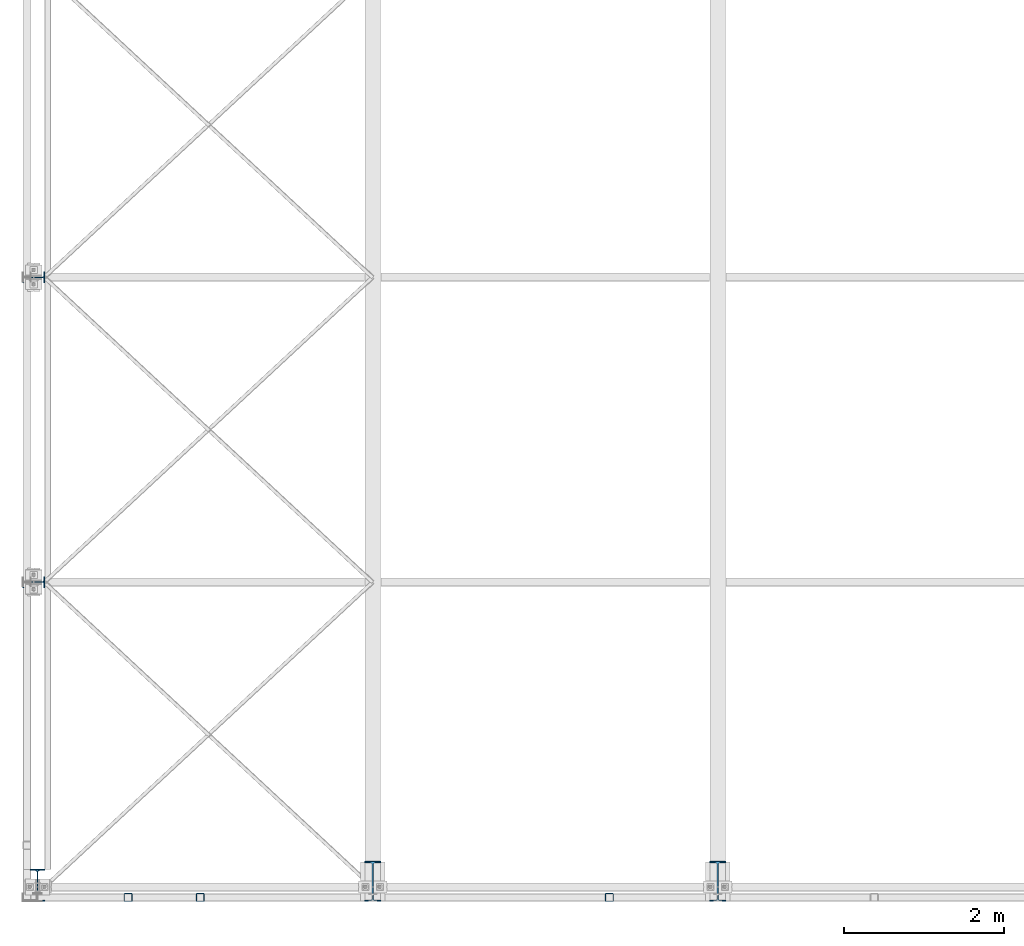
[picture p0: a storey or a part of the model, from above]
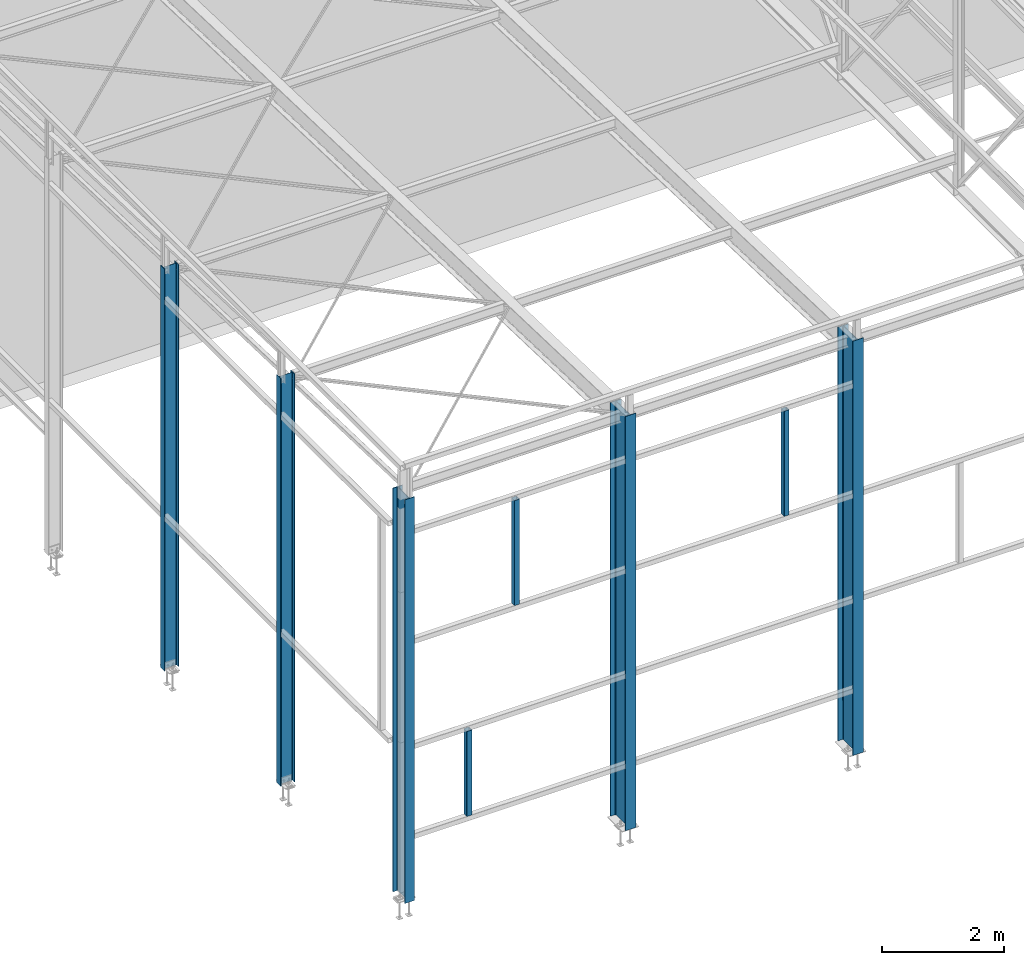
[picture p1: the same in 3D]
Properties of the parts of a building model (IFC2X3), part 1 of 2

# File
Description: ViewDefinition[CoordinationView_V2.0, QuantityTakeOffAddOnView]
File name: V.ifc
Time: 2017-08-30T17:55:49
Author: Gaël\Gaël_P
Organization: Structural Designer
Written by: IFC Database Version:Work
Made in: Tekla Structures 2016i Service Pack 3, IFC Export Version: 4.0.0.0 Jan 30 2017

# IfcSite, Undefined
RefElevation: 0 mm

# IfcBuildingStorey, Undefined
In: Undefined
Elevation: 0 mm

# IfcBeam: 4550*200 (2)
In: Undefined
Description: 4550*200; Material: CONCRETE/C25/30
Pset_BeamCommon - LoadBearing: yes; Reference: Po0(?)
Tekla Commun - Niveau bas: +0.000; Niveau haut: +4.550; Repère de pièce: Po0(?); Repère d'assemblage: Po0(?); Phase: 1; Classe: 1; Matériau: C25/30; Profil: 4550*200; Nom: POUTRE
Tekla Quantités - Surface par tonne: 4.4 m2; Hauteur: 4550 mm; Largeur: 200 mm
Name | Poids (kg) = NetWeight (kg) | Volume (m3) | Surface supérieure totale (m2) | Surface nette (m2) | Longueur (mm) | Length (mm) | OuterSurfaceArea (m2) | NetVolume (m3)
POUTRE | 29789.8 | 12.4 | 2.7 | 131.7 | 13732.4 | 13732.4 | 131.729 | 12.4124
POUTRE | 20484.3 | 8.5 | 1.9 | 91.3 | 9479.6 | 9479.56 | 91.2546 | 8.53511

# IfcBeam: 8550*200 (5)
In: Undefined
Description: 8550*200; Material: CONCRETE/C25/30
Tekla Commun - Niveau bas: +0.000; Niveau haut: +8.550; Repère de pièce: Po0(?); Repère d'assemblage: Po0(?); Phase: 1; Classe: 1; Matériau: C25/30; Profil: 8550*200; Nom: POUTRE
Tekla Quantités - Hauteur: 8550 mm; Largeur: 200 mm
Pset_BeamCommon - LoadBearing: yes; Reference: Po0(?)
Name | Poids (kg) = NetWeight (kg) | Volume (m3) | Surface supérieure totale (m2) | Surface par tonne (m2) | Surface nette (m2) | Longueur (mm) = Length (mm) | OuterSurfaceArea (m2) | NetVolume (m3)
POUTRE | 37962 | 15.8 | 1.9 | 4.4 | 165.3 | 9250 | 165.295 | 15.8175
POUTRE | 38372.4 | 16 | 1.9 | 4.4 | 167.8 | 9450 | 167.753 | 15.9885
POUTRE | 141998 | 59.2 | 6.9 | 4.3 | 610.3 | 34800 | 610.337 | 59.166
POUTRE | 38782.8 | 16.2 | 1.9 | 4.4 | 170.2 | 9650 | 170.212 | 16.1595
POUTRE | 201869 | 84.1 | 9.8 | 4.3 | 864.9 | 49296.2 | 864.929 | 84.112

# IfcBeam: HEA140 (4)
In: Undefined
Description: HEA140; Material: STEEL/S275-E28
Pset_BeamCommon - LoadBearing: yes
Tekla Commun - Repère d'assemblage: L0(?); Phase: 1; Classe: 2; Matériau: S275-E28; Profil: HEA140; Nom: LONGERON
Tekla Quantités - Volume: 0 m3; Surface par tonne: 32.2 m2; Hauteur: 133 mm; Largeur: 140 mm
Name | Reference = Repère de pièce | Niveau bas | Niveau haut | Poids (kg) | Surface supérieure totale (m2) | Surface nette (m2) | Longueur (mm) = Length (mm) | OuterSurfaceArea (m2) | NetVolume (m3) | NetWeight (kg)
LONGERON | L0 | +10.423 | +10.556 | 382.8 | 2.2 | 12.7 | 15520 | 12.3229 | 0.0468394 | 367.689
LONGERON | L0 | +11.236 | +11.369 | 382.8 | 2.2 | 12.7 | 15520 | 12.3229 | 0.0468394 | 367.689
LONGERON | L0 | +12.037 | +12.170 | 382.8 | 2.2 | 12.7 | 15520 | 12.3229 | 0.0468394 | 367.689
LONGERON | L0(?) | +7.117 | +7.250 | 371 | 2.1 | 12.3 | 15040 | 11.9418 | 0.0453907 | 356.317

# IfcBeam: HEA180, LONGERON
In: Undefined
Description: HEA180; Material: STEEL/S275-E28
Pset_BeamCommon - LoadBearing: yes; Reference: L0
Tekla Commun - Niveau bas: +7.079; Niveau haut: +7.250; Repère de pièce: L0; Repère d'assemblage: L0(?); Phase: 1; Classe: 2; Matériau: S275-E28; Profil: HEA180; Nom: LONGERON
Tekla Quantités - Poids: 545.3 kg; Volume: 0.1 m3; Surface supérieure totale: 2.8 m2; Surface par tonne: 28.8 m2; Surface nette: 16.1 m2; Hauteur: 171 mm; Largeur: 180 mm; Longueur: 15350 mm
BaseQuantities - Length: 15350 mm; OuterSurfaceArea: 15.7184 m2; NetVolume: 0.0664962 m3; NetWeight: 521.995 kg

# IfcBeam: HEA200, LONGERON
In: Undefined
Description: HEA200; Material: STEEL/S275-E28
Pset_BeamCommon - LoadBearing: yes; Reference: L0(?)
Tekla Commun - Niveau bas: +7.060; Niveau haut: +7.250; Repère de pièce: L0(?); Repère d'assemblage: L0(?); Phase: 1; Classe: 2; Matériau: S275-E28; Profil: HEA200; Nom: LONGERON
Tekla Quantités - Poids: 648.6 kg; Volume: 0.1 m3; Surface supérieure totale: 3.1 m2; Surface par tonne: 26.9 m2; Surface nette: 17.9 m2; Hauteur: 190 mm; Largeur: 200 mm; Longueur: 15350 mm
BaseQuantities - Length: 15350 mm; OuterSurfaceArea: 17.4376 m2; NetVolume: 0.0783617 m3; NetWeight: 615.14 kg

# IfcBeam: IPE120 (7)
In: Undefined
Description: IPE120; Material: STEEL/S275-E28
Tekla Commun - Repère d'assemblage: PN0(?); Phase: 1; Classe: 2; Matériau: S275-E28; Profil: IPE120; Nom: PANNE
Tekla Quantités - Volume: 0 m3; Surface supérieure totale: 0 m2; Surface par tonne: 45.8 m2; Hauteur: 120 mm; Largeur: 64 mm
Pset_BeamCommon - LoadBearing: yes
Name | Niveau bas | Niveau haut | Repère de pièce = Reference | Poids (kg) | Surface nette (m2) | Longueur (mm) = Length (mm) | OuterSurfaceArea (m2) | NetVolume (m3) | NetWeight (kg)
PANNE | +3.188 | +3.311 | PN0 | 114 | 5.4 | 11000 | 5.225 | 0.0140686 | 110.438 | Tekla Commun - Finition: GALVA
PANNE | +3.083 | +3.206 | PN0 | 114 | 5.4 | 11000 | 5.225 | 0.0140686 | 110.438 | Tekla Commun - Finition: GALVA
PANNE | +2.978 | +3.102 | PN0 | 114 | 5.4 | 11000 | 5.225 | 0.0140686 | 110.438 | Tekla Commun - Finition: GALVA
PANNE | +7.451 | +7.573 | PN0(?) | 11.6 | 0.5 | 1120 | 0.532 | 0.00143244 | 11.2446
PANNE | +7.571 | +7.693 | PN0(?) | 11.6 | 0.5 | 1120 | 0.532 | 0.00143244 | 11.2446
PANNE | +7.690 | +7.812 | PN0(?) | 11.6 | 0.5 | 1120 | 0.532 | 0.00143244 | 11.2446
PANNE | +7.810 | +7.932 | PN0(?) | 11.6 | 0.5 | 1120 | 0.532 | 0.00143244 | 11.2446

# IfcBeam: IPE160 (4)
In: Undefined
Description: IPE160; Material: STEEL/S275-E28
Tekla Commun - Niveau bas: +2.816; Niveau haut: +3.200; Repère de pièce: T0; Repère d'assemblage: T0(?); Finition: GALVA; Phase: 1; Classe: 2; Matériau: S275-E28; Profil: IPE160; Nom: TRAVERSE
Tekla Quantités - Poids: 67.7 kg; Volume: 0 m3; Surface supérieure totale: 0 m2; Surface par tonne: 39.5 m2; Surface nette: 2.7 m2; Hauteur: 160 mm; Largeur: 82 mm; Longueur: 4294.2 mm
Pset_BeamCommon - LoadBearing: yes; Reference: T0
BaseQuantities - Length: 4294.25 mm; OuterSurfaceArea: 2.67532 m2; NetVolume: 0.00831287 m3; NetWeight: 65.256 kg

# IfcBeam: IPE180 (5)
In: Undefined
Description: IPE180; Material: STEEL/S275-E28
Pset_BeamCommon - LoadBearing: yes; Reference: PN0(?)
Tekla Commun - Repère de pièce: PN0(?); Repère d'assemblage: PN0(?); Phase: 1; Classe: 2; Matériau: S275-E28; Profil: IPE180; Nom: PANNE
Tekla Quantités - Poids: 70 kg; Volume: 0 m3; Surface supérieure totale: 0 m2; Surface par tonne: 37.2 m2; Surface nette: 2.7 m2; Hauteur: 180 mm; Largeur: 91 mm; Longueur: 3730 mm
BaseQuantities - Length: 3730 mm; OuterSurfaceArea: 2.60354 m2; NetVolume: 0.008673 m3; NetWeight: 68.083 kg
Name | Niveau bas | Niveau haut
PANNE | +7.391 | +7.574
PANNE | +7.510 | +7.693
PANNE | +7.630 | +7.813
PANNE | +7.749 | +7.932
PANNE | +7.862 | +8.045

# IfcBeam: IPE200 (20)
In: Undefined
Description: IPE200; Material: STEEL/S275-E28
Pset_BeamCommon - LoadBearing: yes; Reference: PN0(?)
Tekla Commun - Repère de pièce: PN0(?); Repère d'assemblage: PN0(?); Phase: 1; Classe: 2; Matériau: S275-E28; Profil: IPE200; Nom: PANNE
Tekla Quantités - Volume: 0 m3; Surface supérieure totale: 0 m2; Surface par tonne: 34.3 m2; Hauteur: 200 mm; Largeur: 100 mm
Name | Niveau bas | Niveau haut | Poids (kg) | Surface nette (m2) | Longueur (mm) = Length (mm) | OuterSurfaceArea (m2) | NetVolume (m3) | NetWeight (kg)
PANNE | +7.371 | +7.574 | 116.6 | 4.2 | 5210 | 4.00128 | 0.0141962 | 111.44
PANNE | +7.490 | +7.693 | 116.6 | 4.2 | 5210 | 4.00128 | 0.0141962 | 111.44
PANNE | +7.610 | +7.813 | 116.6 | 4.2 | 5210 | 4.00128 | 0.0141962 | 111.44
PANNE | +7.729 | +7.932 | 116.6 | 4.2 | 5210 | 4.00128 | 0.0141962 | 111.44
PANNE | +7.848 | +8.051 | 114 | 4 | 5090 | 3.90912 | 0.0138692 | 108.873
PANNE | +7.371 | +7.574 | 89.9 | 3.2 | 4020 | 3.08736 | 0.0109537 | 85.9865
PANNE | +7.371 | +7.574 | 91.5 | 3.2 | 4090 | 3.14112 | 0.0111444 | 87.4838
PANNE | +7.490 | +7.693 | 89.9 | 3.2 | 4020 | 3.08736 | 0.0109537 | 85.9865
PANNE | +7.490 | +7.693 | 91.5 | 3.2 | 4090 | 3.14112 | 0.0111444 | 87.4838
PANNE | +7.610 | +7.813 | 89.9 | 3.2 | 4020 | 3.08736 | 0.0109537 | 85.9865
PANNE | +7.610 | +7.813 | 91.5 | 3.2 | 4090 | 3.14112 | 0.0111444 | 87.4838
PANNE | +7.729 | +7.932 | 89.9 | 3.2 | 4020 | 3.08736 | 0.0109537 | 85.9865
PANNE | +7.729 | +7.932 | 91.5 | 3.2 | 4090 | 3.14112 | 0.0111444 | 87.4838
PANNE | +7.848 | +8.051 | 84.7 | 3 | 3785 | 2.90688 | 0.0103134 | 80.9599
PANNE | +7.848 | +8.051 | 91.5 | 3.2 | 4090 | 3.14112 | 0.0111444 | 87.4838
PANNE | +7.729 | +7.932 | 88.9 | 3.1 | 3975 | 3.0528 | 0.0108311 | 85.024
PANNE | +7.610 | +7.813 | 88.9 | 3.1 | 3975 | 3.0528 | 0.0108311 | 85.024
PANNE | +7.490 | +7.693 | 88.9 | 3.1 | 3975 | 3.0528 | 0.0108311 | 85.024
PANNE | +7.374 | +7.577 | 92.3 | 3.3 | 4125 | 3.168 | 0.0112398 | 88.2324
PANNE | +7.848 | +8.051 | 92.3 | 3.3 | 4125 | 3.168 | 0.0112398 | 88.2324

# IfcBeam: IPE270 (2)
In: Undefined
Description: IPE270; Material: STEEL/S275-E28
Pset_BeamCommon - LoadBearing: yes
Tekla Commun - Phase: 1; Classe: 2; Matériau: S275-E28; Profil: IPE270
Tekla Quantités - Surface supérieure totale: 0 m2; Surface par tonne: 28.9 m2; Hauteur: 270 mm; Largeur: 135 mm
Name | Reference = Repère de pièce = Repère d'assemblage | Niveau bas | Niveau haut | Nom | Poids (kg) | Volume (m3) | Surface nette (m2) | Longueur (mm) = Length (mm) | OuterSurfaceArea (m2) | NetVolume (m3) | NetWeight (kg)
PANNE | PN0(?) | +7.778 | +8.052 | PANNE | 190.1 | 0 | 5.6 | 5275 | 5.49128 | 0.0232172 | 182.255
TRAVERSE | T0(?) | +7.297 | +8.040 | TRAVERSE | 542.6 | 0.1 | 16.1 | 15058.6 | 15.676 | 0.0662368 | 519.959

# IfcBeam: IPE450 (3)
In: Undefined
Description: IPE450; Material: STEEL/S275-E28
Tekla Commun - Niveau bas: +7.117; Repère de pièce: T0(?); Repère d'assemblage: T0(?); Phase: 1; Classe: 2; Matériau: S275-E28; Profil: IPE450; Nom: TRAVERSE
Tekla Quantités - Surface supérieure totale: 0 m2; Surface par tonne: 20.7 m2; Hauteur: 450 mm; Largeur: 190 mm
Pset_BeamCommon - LoadBearing: yes; Reference: T0(?)
Name | Niveau haut | Poids (kg) | Volume (m3) | Surface nette (m2) | Longueur (mm) = Length (mm) | OuterSurfaceArea (m2) | NetVolume (m3) | NetWeight (kg)
2 x TRAVERSE | +8.040 | 1168.1 | 0.1 | 24.7 | 15061.6 | 24.1738 | 0.143004 | 1122.58
TRAVERSE | +8.050 | 1192.2 | 0.2 | 25.2 | 15371.6 | 24.6714 | 0.146009 | 1146.17

# IfcBeam: IPE550 (2)
In: Undefined
Description: IPE550; Material: STEEL/S275-E28
Pset_BeamCommon - LoadBearing: yes; Reference: T0(?)
Tekla Commun - Niveau bas: +7.017; Repère de pièce: T0(?); Repère d'assemblage: T0(?); Phase: 1; Classe: 2; Matériau: S275-E28; Profil: IPE550; Nom: TRAVERSE
Tekla Quantités - Volume: 0.2 m3; Surface supérieure totale: 0 m2; Surface par tonne: 17.8 m2; Hauteur: 550 mm; Largeur: 210 mm
Name | Niveau haut | Poids (kg) | Surface nette (m2) | Longueur (mm) = Length (mm) | OuterSurfaceArea (m2) | NetVolume (m3) | NetWeight (kg)
TRAVERSE | +8.047 | 1608.9 | 29.3 | 15294.8 | 28.7084 | 0.197801 | 1552.74
TRAVERSE | +8.050 | 1617.3 | 29.5 | 15374.9 | 28.8586 | 0.198949 | 1561.75

# IfcBeam: L100*10 (6)
In: Undefined
Description: L100*10; Material: STEEL/S235-E24
Pset_BeamCommon - LoadBearing: yes
Tekla Commun - Repère d'assemblage: A0(?); Phase: 1; Classe: 2; Matériau: S235-E24; Profil: L100*10; Nom: ATTACHE
Tekla Quantités - Volume: 0 m3; Surface supérieure totale: 0 m2; Surface par tonne: 25.9 m2; Surface nette: 0.1 m2; Hauteur: 100 mm; Largeur: 100 mm
Name | Reference = Repère de pièce | Niveau bas | Niveau haut | Poids (kg) | Longueur (mm) = Length (mm) | OuterSurfaceArea (m2) | NetVolume (m3) | NetWeight (kg)
2 x ATTACHE | A0(?) | +7.203 | +7.483 | 4.2 | 280 | 0.1092 | 0.000532 | 4.1762
3 x ATTACHE | A0 | +7.970 | +8.210 | 3.6 | 240 | 0.0936 | 0.000456 | 3.5796
ATTACHE | A0 | +7.240 | +7.420 | 2.7 | 180 | 0.0702 | 0.000342 | 2.6847

# IfcBeam: L150*15 (14)
In: Undefined
Description: L150*15; Material: STEEL/S235-E24
Pset_BeamCommon - LoadBearing: yes; Reference: A0
Tekla Commun - Niveau bas: -0.250; Niveau haut: -0.100; Repère de pièce: A0; Repère d'assemblage: A0(?); Phase: 1; Classe: 2; Matériau: S235-E24; Profil: L150*15; Nom: ATTACHE
Tekla Quantités - Volume: 0 m3; Surface supérieure totale: 0 m2; Surface par tonne: 17.4 m2; Surface nette: 0.1 m2; Hauteur: 150 mm; Largeur: 150 mm
Name | Poids (kg) | Longueur (mm) = Length (mm) | OuterSurfaceArea (m2) | NetVolume (m3) | NetWeight (kg)
4 x ATTACHE | 4.2 | 120 | 0.07032 | 0.000513 | 4.02705 | Tekla Commun - Finition: GALVA
10 x ATTACHE | 6.8 | 200 | 0.1172 | 0.000855 | 6.71175

# IfcBeam: L40*4 (4)
In: Undefined
Description: L40*4; Material: STEEL/S235-E24
Pset_BeamCommon - LoadBearing: yes; Reference: S0
Tekla Commun - Repère de pièce: S0; Repère d'assemblage: S0(?); Finition: GALVA; Phase: 1; Classe: 2; Matériau: S235-E24; Profil: L40*4; Nom: STABILITE CVT
Tekla Quantités - Volume: 0 m3; Surface supérieure totale: 0 m2; Surface par tonne: 64.1 m2; Hauteur: 40 mm; Largeur: 40 mm
Name | Niveau bas | Niveau haut | Poids (kg) | Surface nette (m2) | Longueur (mm) | Length (mm) | OuterSurfaceArea (m2) | NetVolume (m3) | NetWeight (kg)
2 x STABILITE CVT | +2.938 | +3.198 | 10.1 | 0.6 | 4200 | 4200 | 0.651001 | 0.0012768 | 10.0229
STABILITE CVT | +2.941 | +3.190 | 12.1 | 0.9 | 5065 | 5064.97 | 0.78507 | 0.00153975 | 12.087
STABILITE CVT | +2.939 | +3.190 | 12.1 | 0.9 | 5065 | 5064.97 | 0.78507 | 0.00153975 | 12.087

# IfcBeam: L50*5 (27)
In: Undefined
Description: L50*5; Material: STEEL/S235-E24
Pset_BeamCommon - LoadBearing: yes
Tekla Commun - Repère d'assemblage: S0(?); Phase: 1; Classe: 2; Matériau: S235-E24; Profil: L50*5
Tekla Quantités - Volume: 0 m3; Surface par tonne: 51.5 m2; Hauteur: 50 mm; Largeur: 50 mm
Name | Reference = Repère de pièce | Niveau bas | Niveau haut | Nom | Poids (kg) | Surface supérieure totale (m2) | Surface nette (m2) | Longueur (mm) | Length (mm) | OuterSurfaceArea (m2) | NetVolume (m3) | NetWeight (kg)
3 x SUPPORT | S0 | +8.050 | +8.100 | SUPPORT | 57.2 | 0.8 | 3 | 15180 | 15180 | 2.94492 | 0.0072105 | 56.6024
STABILITE CVT | S0(?) | +7.447 | +7.617 | STABILITE CVT | 21.2 | 0 | 1.1 | 5616.1 | 5616.06 | 1.08952 | 0.00266763 | 20.9409
STABILITE CVT | S0(?) | +7.447 | +7.616 | STABILITE CVT | 21.2 | 0 | 1.1 | 5616.1 | 5616.06 | 1.08952 | 0.00266763 | 20.9409
STABILITE CVT | S0(?) | +7.447 | +7.617 | STABILITE CVT | 21.6 | 0 | 1.1 | 5739.7 | 5739.71 | 1.1135 | 0.00272636 | 21.4019
STABILITE CVT | S0(?) | +7.447 | +7.616 | STABILITE CVT | 21.6 | 0 | 1.1 | 5739.7 | 5739.71 | 1.1135 | 0.00272636 | 21.4019
STABILITE CVT | S0(?) | +7.450 | +7.616 | STABILITE CVT | 20.8 | 0 | 1.1 | 5523.2 | 5523.2 | 1.0715 | 0.00262352 | 20.5946
STABILITE CVT | S0(?) | +7.450 | +7.617 | STABILITE CVT | 20.8 | 0 | 1.1 | 5523.2 | 5523.2 | 1.0715 | 0.00262352 | 20.5946
STABILITE CVT | S0(?) | +7.566 | +7.736 | STABILITE CVT | 21 | 0 | 1.1 | 5584.1 | 5584.12 | 1.08332 | 0.00265246 | 20.8218
STABILITE CVT | S0(?) | +7.566 | +7.737 | STABILITE CVT | 21 | 0 | 1.1 | 5584.1 | 5584.12 | 1.08332 | 0.00265246 | 20.8218
STABILITE CVT | S0(?) | +7.686 | +7.855 | STABILITE CVT | 21 | 0 | 1.1 | 5584.1 | 5584.11 | 1.08332 | 0.00265245 | 20.8218
STABILITE CVT | S0(?) | +7.686 | +7.856 | STABILITE CVT | 21 | 0 | 1.1 | 5584.1 | 5584.11 | 1.08332 | 0.00265245 | 20.8218
STABILITE CVT | S0(?) | +7.805 | +7.974 | STABILITE CVT | 21 | 0 | 1.1 | 5584.1 | 5584.12 | 1.08332 | 0.00265246 | 20.8218
STABILITE CVT | S0(?) | +7.805 | +7.976 | STABILITE CVT | 21 | 0 | 1.1 | 5584.1 | 5584.12 | 1.08332 | 0.00265246 | 20.8218
2 x STABILITE CVT | S0 | +8.456 | +10.494 | STABILITE CVT | 33.3 | 0 | 1.7 | 8839 | 8838.98 | 1.71476 | 0.00419852 | 32.9583
2 x STABILITE CVT | S0 | +8.456 | +10.511 | STABILITE CVT | 33.3 | 0 | 1.7 | 8839 | 8838.98 | 1.71476 | 0.00419852 | 32.9583
2 x STABILITE CVT | S0 | +8.458 | +11.324 | STABILITE CVT | 36.7 | 0 | 1.9 | 9741 | 9741.02 | 1.88976 | 0.00462698 | 36.3218
2 x STABILITE CVT | S0 | +8.474 | +11.324 | STABILITE CVT | 36.7 | 0 | 1.9 | 9741 | 9741.02 | 1.88976 | 0.00462698 | 36.3218
2 x STABILITE CVT | S0 | +8.447 | +12.101 | STABILITE CVT | 40.9 | 0 | 2.2 | 10856.9 | 10856.9 | 2.10624 | 0.00515703 | 40.4827
2 x STABILITE CVT | S0 | +8.462 | +12.101 | STABILITE CVT | 40.9 | 0 | 2.2 | 10856.9 | 10856.9 | 2.10624 | 0.00515703 | 40.4827

# IfcBeam: L80*8, ATTACHE
In: Undefined
Description: L80*8; Material: STEEL/S235-E24
Pset_BeamCommon - LoadBearing: yes; Reference: A0
Tekla Commun - Niveau bas: +3.255; Niveau haut: +3.375; Repère de pièce: A0; Repère d'assemblage: A0(?); Phase: 1; Classe: 2; Matériau: S235-E24; Profil: L80*8; Nom: ATTACHE
Tekla Quantités - Poids: 1.2 kg; Volume: 0 m3; Surface supérieure totale: 0 m2; Surface par tonne: 32.2 m2; Surface nette: 0 m2; Hauteur: 80 mm; Largeur: 80 mm; Longueur: 120 mm
BaseQuantities - Length: 120 mm; OuterSurfaceArea: 0.03732 m2; NetVolume: 0.00014592 m3; NetWeight: 1.14547 kg

# IfcBeam: PL10*100 (2)
In: Undefined
Description: PL10*100; Material: STEEL/S235-E24
Tekla Commun - Niveau bas: +8.450; Niveau haut: +8.550; Repère de pièce: A0; Repère d'assemblage: A0(?); Phase: 1; Classe: 2; Matériau: S235-E24; Profil: PL10*100; Nom: ATTACHE
Tekla Quantités - Poids: 2.2 kg; Volume: 0 m3; Surface supérieure totale: 0 m2; Surface par tonne: 28.9 m2; Surface nette: 0.1 m2; Hauteur: 100 mm; Largeur: 10 mm; Longueur: 270 mm
Pset_BeamCommon - LoadBearing: yes; Reference: A0
BaseQuantities - Length: 270 mm; OuterSurfaceArea: 0.0636 m2; NetVolume: 0.00028 m3; NetWeight: 2.198 kg

# IfcBeam: PL10*135, ATTACHE
In: Undefined
Description: PL10*135; Material: STEEL/S235-E24
Pset_BeamCommon - LoadBearing: yes; Reference: A0
Tekla Commun - Niveau bas: +7.092; Niveau haut: +7.196; Repère de pièce: A0; Repère d'assemblage: A0(?); Phase: 1; Classe: 2; Matériau: S235-E24; Profil: PL10*135; Nom: ATTACHE
Tekla Quantités - Poids: 2 kg; Volume: 0 m3; Surface supérieure totale: 0 m2; Surface par tonne: 28.8 m2; Surface nette: 0.1 m2; Hauteur: 135 mm; Largeur: 10 mm; Longueur: 180.6 mm
BaseQuantities - Length: 180.705 mm; OuterSurfaceArea: 0.0579048 m2; NetVolume: 0.000256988 m3; NetWeight: 2.01735 kg

# IfcBeam: PL10*190 (2)
In: Undefined
Description: PL10*190; Material: STEEL/S235-E24
Tekla Commun - Niveau bas: +7.016; Niveau haut: +7.119; Repère de pièce: A0(?); Repère d'assemblage: A0(?); Phase: 1; Classe: 2; Matériau: S235-E24; Profil: PL10*190; Nom: ATTACHE
Tekla Quantités - Poids: 2.8 kg; Volume: 0 m3; Surface supérieure totale: 0 m2; Surface par tonne: 28.2 m2; Surface nette: 0.1 m2; Hauteur: 190 mm; Largeur: 10 mm; Longueur: 180.6 mm
Pset_BeamCommon - LoadBearing: yes; Reference: A0(?)
BaseQuantities - Length: 180.619 mm; OuterSurfaceArea: 0.0799237 m2; NetVolume: 0.000361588 m3; NetWeight: 2.83846 kg

# IfcBeam: PL3*1640 (2)
In: Undefined
Description: PL3*1640; Material: STEEL/S235-E24
Pset_BeamCommon - LoadBearing: yes; Reference: F0
Tekla Commun - Niveau bas: +2.926; Niveau haut: +2.982; Repère de pièce: F0; Repère d'assemblage: F0(?); Finition: GALVA; Phase: 1; Classe: 2; Matériau: S235-E24; Profil: PL3*1640; Nom: FEUILLURE
Tekla Quantités - Poids: 6.5 kg; Volume: 0 m3; Surface supérieure totale: 0 m2; Surface par tonne: 86.6 m2; Surface nette: 0.6 m2; Hauteur: 1640 mm; Largeur: 3 mm; Longueur: 164.3 mm
BaseQuantities - Length: 164.306 mm; OuterSurfaceArea: 0.559105 m2; NetVolume: 0.000822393 m3; NetWeight: 6.45578 kg

# IfcBeam: PL3*75 (6)
In: Undefined
Description: PL3*75; Material: STEEL/S235-E24
Tekla Commun - Repère d'assemblage: 0(?); Phase: 1; Classe: 2; Matériau: S235-E24; Profil: PL3*75; Nom: RAIDISSEUR
Tekla Quantités - Poids: 0.3 kg; Volume: 0 m3; Surface supérieure totale: 0 m2; Surface par tonne: 90 m2; Surface nette: 0 m2; Hauteur: 75 mm; Largeur: 3 mm; Longueur: 169.7 mm
Pset_BeamCommon - LoadBearing: yes
BaseQuantities - Length: 169.7 mm; OuterSurfaceArea: 0.024596 m2; NetVolume: 0.0000347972 m3; NetWeight: 0.273158 kg
Name | Niveau bas | Niveau haut | Repère de pièce = Reference
RAIDISSEUR | +6.088 | +6.091 | 0(?)
RAIDISSEUR | +3.869 | +3.872 | 0(?)
RAIDISSEUR | +6.898 | +6.901 | 0
RAIDISSEUR | +5.279 | +5.282 | 0(?)
RAIDISSEUR | +4.679 | +4.682 | 0(?)
RAIDISSEUR | +3.059 | +3.062 | 0(?)

# IfcBeam: PL5*1050, FEUILLURE
In: Undefined
Description: PL5*1050; Material: STEEL/S235-E24
Tekla Commun - Niveau bas: +7.390; Niveau haut: +8.440; Repère de pièce: F0(?); Repère d'assemblage: F0(?); Phase: 1; Classe: 2; Matériau: S235-E24; Profil: PL5*1050; Nom: FEUILLURE
Tekla Quantités - Poids: 9.9 kg; Volume: 0 m3; Surface supérieure totale: 0 m2; Surface par tonne: 52.3 m2; Surface nette: 0.5 m2; Hauteur: 1050 mm; Largeur: 5 mm; Longueur: 235 mm
Pset_BeamCommon - LoadBearing: yes; Reference: F0(?)
BaseQuantities - Length: 235 mm; OuterSurfaceArea: 0.5169 m2; NetVolume: 0.00126 m3; NetWeight: 9.891 kg

# IfcBeam: PL5*1250, FEUILLURE
In: Undefined
Description: PL5*1250; Material: STEEL/S235-E24
Tekla Commun - Niveau bas: +8.577; Niveau haut: +9.201; Repère de pièce: F0; Repère d'assemblage: F0(?); Phase: 1; Classe: 2; Matériau: S235-E24; Profil: PL5*1250; Nom: FEUILLURE
Tekla Quantités - Poids: 11.8 kg; Volume: 0 m3; Surface supérieure totale: 0 m2; Surface par tonne: 52.2 m2; Surface nette: 0.6 m2; Hauteur: 1250 mm; Largeur: 5 mm; Longueur: 235 mm
Pset_BeamCommon - LoadBearing: yes; Reference: F0
BaseQuantities - Length: 235 mm; OuterSurfaceArea: 0.6149 m2; NetVolume: 0.0015 m3; NetWeight: 11.775 kg

# IfcBeam: PL5*1340, FEUILLURE
In: Undefined
Description: PL5*1340; Material: STEEL/S235-E24
Pset_BeamCommon - LoadBearing: yes; Reference: F0(?)
Tekla Commun - Niveau bas: +6.000; Niveau haut: +7.340; Repère de pièce: F0(?); Repère d'assemblage: F0(?); Phase: 1; Classe: 2; Matériau: S235-E24; Profil: PL5*1340; Nom: FEUILLURE
Tekla Quantités - Poids: 11.8 kg; Volume: 0 m3; Surface supérieure totale: 0 m2; Surface par tonne: 52.3 m2; Surface nette: 0.6 m2; Hauteur: 1340 mm; Largeur: 5 mm; Longueur: 220 mm
BaseQuantities - Length: 220 mm; OuterSurfaceArea: 0.61865 m2; NetVolume: 0.0015075 m3; NetWeight: 11.8339 kg

# IfcBeam: PL5*1550, FEUILLURE
In: Undefined
Description: PL5*1550; Material: STEEL/S235-E24
Pset_BeamCommon - LoadBearing: yes; Reference: F0
Tekla Commun - Niveau bas: +8.565; Niveau haut: +9.355; Repère de pièce: F0; Repère d'assemblage: F0(?); Phase: 1; Classe: 2; Matériau: S235-E24; Profil: PL5*1550; Nom: FEUILLURE
Tekla Quantités - Poids: 14.3 kg; Volume: 0 m3; Surface supérieure totale: 0 m2; Surface par tonne: 52.2 m2; Surface nette: 0.6 m2; Hauteur: 1550 mm; Largeur: 5 mm; Longueur: 230 mm
BaseQuantities - Length: 230 mm; OuterSurfaceArea: 0.74635 m2; NetVolume: 0.00182125 m3; NetWeight: 14.2968 kg

# IfcBeam: PL5*1680, FEUILLURE
In: Undefined
Description: PL5*1680; Material: STEEL/S235-E24
Pset_BeamCommon - LoadBearing: yes; Reference: F0(?)
Tekla Commun - Niveau bas: +6.000; Niveau haut: +7.680; Repère de pièce: F0(?); Repère d'assemblage: F0(?); Phase: 1; Classe: 2; Matériau: S235-E24; Profil: PL5*1680; Nom: FEUILLURE
Tekla Quantités - Poids: 14.8 kg; Volume: 0 m3; Surface supérieure totale: 0 m2; Surface par tonne: 52.2 m2; Surface nette: 0.9 m2; Hauteur: 1680 mm; Largeur: 5 mm; Longueur: 220 mm
BaseQuantities - Length: 220 mm; OuterSurfaceArea: 0.77505 m2; NetVolume: 0.00189 m3; NetWeight: 14.8365 kg

# IfcBeam: PL5*1700, FEUILLURE
In: Undefined
Description: PL5*1700; Material: STEEL/S235-E24
Pset_BeamCommon - LoadBearing: yes; Reference: F0
Tekla Commun - Niveau bas: +8.560; Niveau haut: +10.260; Repère de pièce: F0; Repère d'assemblage: F0(?); Phase: 1; Classe: 2; Matériau: S235-E24; Profil: PL5*1700; Nom: FEUILLURE
Tekla Quantités - Poids: 15.7 kg; Volume: 0 m3; Surface supérieure totale: 0 m2; Surface par tonne: 52.2 m2; Surface nette: 0.9 m2; Hauteur: 1700 mm; Largeur: 5 mm; Longueur: 230 mm
BaseQuantities - Length: 230 mm; OuterSurfaceArea: 0.81835 m2; NetVolume: 0.0019975 m3; NetWeight: 15.6804 kg

# IfcBeam: PL5*1750, FEUILLURE
In: Undefined
Description: PL5*1750; Material: STEEL/S235-E24
Pset_BeamCommon - LoadBearing: yes; Reference: F0
Tekla Commun - Niveau bas: +10.260; Niveau haut: +12.010; Repère de pièce: F0; Repère d'assemblage: F0(?); Phase: 1; Classe: 2; Matériau: S235-E24; Profil: PL5*1750; Nom: FEUILLURE
Tekla Quantités - Poids: 16.1 kg; Volume: 0 m3; Surface supérieure totale: 0 m2; Surface par tonne: 52.2 m2; Surface nette: 0.9 m2; Hauteur: 1750 mm; Largeur: 5 mm; Longueur: 230 mm
BaseQuantities - Length: 230 mm; OuterSurfaceArea: 0.84235 m2; NetVolume: 0.00205625 m3; NetWeight: 16.1416 kg

# IfcBeam: PL5*1840, FEUILLURE
In: Undefined
Description: PL5*1840; Material: STEEL/S235-E24
Pset_BeamCommon - LoadBearing: yes; Reference: F0
Tekla Commun - Niveau bas: +8.560; Niveau haut: +10.400; Repère de pièce: F0; Repère d'assemblage: F0(?); Phase: 1; Classe: 2; Matériau: S235-E24; Profil: PL5*1840; Nom: FEUILLURE
Tekla Quantités - Poids: 17 kg; Volume: 0 m3; Surface supérieure totale: 0 m2; Surface par tonne: 52.2 m2; Surface nette: 0.9 m2; Hauteur: 1840 mm; Largeur: 5 mm; Longueur: 230 mm
BaseQuantities - Length: 230 mm; OuterSurfaceArea: 0.88555 m2; NetVolume: 0.002162 m3; NetWeight: 16.9717 kg

# IfcBeam: PL5*2150, FEUILLURE
In: Undefined
Description: PL5*2150; Material: STEEL/S235-E24
Pset_BeamCommon - LoadBearing: yes; Reference: 0
Tekla Commun - Niveau bas: -0.000; Niveau haut: +2.150; Repère de pièce: 0; Repère d'assemblage: 0(?); Phase: 1; Classe: 2; Matériau: S235-E24; Profil: PL5*2150; Nom: FEUILLURE
Tekla Quantités - Poids: 13.9 kg; Volume: 0 m3; Surface supérieure totale: 0 m2; Surface par tonne: 52.6 m2; Surface nette: 0.6 m2; Hauteur: 2150 mm; Largeur: 5 mm; Longueur: 160 mm
BaseQuantities - Length: 160 mm; OuterSurfaceArea: 0.73265 m2; NetVolume: 0.00177375 m3; NetWeight: 13.9239 kg

# IfcBeam: PL5*2220 (2)
In: Undefined
Description: PL5*2220; Material: STEEL/S235-E24
Pset_BeamCommon - LoadBearing: yes; Reference: 0(?)
Tekla Commun - Repère de pièce: 0(?); Repère d'assemblage: 0(?); Phase: 1; Classe: 2; Matériau: S235-E24; Profil: PL5*2220; Nom: FEUILLURE
Tekla Quantités - Poids: 14.3 kg; Volume: 0 m3; Surface supérieure totale: 0 m2; Surface par tonne: 52.6 m2; Surface nette: 0.9 m2; Hauteur: 2220 mm; Largeur: 5 mm; Longueur: 160 mm
BaseQuantities - Length: 160 mm; OuterSurfaceArea: 0.75645 m2; NetVolume: 0.0018315 m3; NetWeight: 14.3773 kg
Name | Niveau bas | Niveau haut
FEUILLURE | +4.980 | +7.200
FEUILLURE | +2.760 | +4.980

# IfcBeam: PL5*2400 (2)
In: Undefined
Description: PL5*2400; Material: STEEL/S235-E24
Pset_BeamCommon - LoadBearing: yes; Reference: F0
Tekla Commun - Niveau bas: +6.020; Niveau haut: +8.420; Repère de pièce: F0; Repère d'assemblage: F0(?); Phase: 1; Classe: 2; Matériau: S235-E24; Profil: PL5*2400; Nom: FEUILLURE
Tekla Quantités - Poids: 19.3 kg; Volume: 0 m3; Surface supérieure totale: 0 m2; Surface par tonne: 52.3 m2; Surface nette: 0.9 m2; Hauteur: 2400 mm; Largeur: 5 mm; Longueur: 200 mm
BaseQuantities - Length: 200 mm; OuterSurfaceArea: 1.01005 m2; NetVolume: 0.00246 m3; NetWeight: 19.311 kg

# IfcBeam: PL5*2650, FEUILLURE
In: Undefined
Description: PL5*2650; Material: STEEL/S235-E24
Pset_BeamCommon - LoadBearing: yes; Reference: F0
Tekla Commun - Niveau bas: +8.560; Niveau haut: +11.210; Repère de pièce: F0; Repère d'assemblage: F0(?); Phase: 1; Classe: 2; Matériau: S235-E24; Profil: PL5*2650; Nom: FEUILLURE
Tekla Quantités - Poids: 24.4 kg; Volume: 0 m3; Surface supérieure totale: 0 m2; Surface par tonne: 52.1 m2; Surface nette: 1.3 m2; Hauteur: 2650 mm; Largeur: 5 mm; Longueur: 230 mm
BaseQuantities - Length: 230 mm; OuterSurfaceArea: 1.27435 m2; NetVolume: 0.00311375 m3; NetWeight: 24.4429 kg

# IfcBeam: PL5*2850, FEUILLURE
In: Undefined
Description: PL5*2850; Material: STEEL/S235-E24
Pset_BeamCommon - LoadBearing: yes; Reference: F0
Tekla Commun - Niveau bas: +8.574; Niveau haut: +9.956; Repère de pièce: F0; Repère d'assemblage: F0(?); Phase: 1; Classe: 2; Matériau: S235-E24; Profil: PL5*2850; Nom: FEUILLURE
Tekla Quantités - Poids: 26.8 kg; Volume: 0 m3; Surface supérieure totale: 0 m2; Surface par tonne: 52.1 m2; Surface nette: 1.5 m2; Hauteur: 2850 mm; Largeur: 5 mm; Longueur: 235 mm
BaseQuantities - Length: 235 mm; OuterSurfaceArea: 1.3989 m2; NetVolume: 0.00342 m3; NetWeight: 26.847 kg

# IfcBeam: PL5*3000 (12)
In: Undefined
Description: PL5*3000; Material: STEEL/S235-E24
Pset_BeamCommon - LoadBearing: yes; Reference: F0
Tekla Commun - Repère de pièce: F0; Repère d'assemblage: F0(?); Phase: 1; Classe: 2; Matériau: S235-E24; Profil: PL5*3000; Nom: FEUILLURE
Tekla Quantités - Volume: 0 m3; Surface supérieure totale: 0 m2; Hauteur: 3000 mm; Largeur: 5 mm
Name | Niveau bas | Niveau haut | Poids (kg) | Surface par tonne (m2) | Surface nette (m2) | Longueur (mm) = Length (mm) | OuterSurfaceArea (m2) | NetVolume (m3) | NetWeight (kg)
FEUILLURE | +9.284 | +10.745 | 27.7 | 52.1 | 1.5 | 230 | 1.44235 | 0.003525 | 27.6713
FEUILLURE | +9.129 | +10.524 | 28.3 | 52.1 | 1.5 | 235 | 1.4724 | 0.0036 | 28.26
FEUILLURE | +9.885 | +11.336 | 28.3 | 52.1 | 1.5 | 235 | 1.4724 | 0.0036 | 28.26
FEUILLURE | +10.674 | +12.136 | 27.7 | 52.1 | 1.5 | 230 | 1.44235 | 0.003525 | 27.6713
2 x FEUILLURE | +3.020 | +6.020 | 24.1 | 52.3 | 1.3 | 200 | 1.26205 | 0.003075 | 24.1388
2 x FEUILLURE | +0.020 | +3.020 | 24.1 | 52.3 | 1.3 | 200 | 1.26205 | 0.003075 | 24.1388
2 x FEUILLURE | +3.000 | +6.000 | 26.5 | 52.2 | 1.5 | 220 | 1.38225 | 0.003375 | 26.4938
FEUILLURE | +0.000 | +3.000 | 26.5 | 52.2 | 1.5 | 220 | 1.38225 | 0.003375 | 26.4938
FEUILLURE | -0.000 | +3.000 | 26.5 | 52.2 | 1.5 | 220 | 1.38225 | 0.003375 | 26.4938

# IfcBeam: PL5*580, FEUILLURE
In: Undefined
Description: PL5*580; Material: STEEL/S235-E24
Pset_BeamCommon - LoadBearing: yes; Reference: F0(?)
Tekla Commun - Niveau bas: +7.860; Niveau haut: +8.440; Repère de pièce: F0(?); Repère d'assemblage: F0(?); Phase: 1; Classe: 2; Matériau: S235-E24; Profil: PL5*580; Nom: FEUILLURE
Tekla Quantités - Poids: 5.5 kg; Volume: 0 m3; Surface supérieure totale: 0 m2; Surface par tonne: 52.5 m2; Surface nette: 0.3 m2; Hauteur: 580 mm; Largeur: 5 mm; Longueur: 235 mm
BaseQuantities - Length: 235 mm; OuterSurfaceArea: 0.2866 m2; NetVolume: 0.000696 m3; NetWeight: 5.4636 kg

# IfcBeam: PL5*75 (3)
In: Undefined
Description: PL5*75; Material: STEEL/S235-E24
Tekla Commun - Repère de pièce: 0; Repère d'assemblage: 0(?); Phase: 1; Classe: 2; Matériau: S235-E24; Profil: PL5*75; Nom: RAIDISSEUR
Tekla Quantités - Poids: 0.5 kg; Volume: 0 m3; Surface supérieure totale: 0 m2; Surface par tonne: 56.1 m2; Surface nette: 0 m2; Hauteur: 75 mm; Largeur: 5 mm; Longueur: 169.7 mm
Pset_BeamCommon - LoadBearing: yes; Reference: 0
BaseQuantities - Length: 169.7 mm; OuterSurfaceArea: 0.0255279 m2; NetVolume: 0.0000579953 m3; NetWeight: 0.455263 kg
Name | Niveau bas | Niveau haut
RAIDISSEUR | +1.047 | +1.052
RAIDISSEUR | +1.897 | +1.902
RAIDISSEUR | +0.197 | +0.202

# IfcBeam: TUBE-C-100*100*4 (49)
In: Undefined
Description: TUBE-C-100*100*4; Material: STEEL/S235-E24
Pset_BeamCommon - LoadBearing: yes
Tekla Commun - Phase: 1; Classe: 2; Matériau: S235-E24; Profil: TUBE-C-100*100*4
Tekla Quantités - Volume: 0 m3; Surface par tonne: 33 m2; Hauteur: 100 mm; Largeur: 100 mm
Name | Reference = Repère de pièce | Niveau bas | Niveau haut | Repère d'assemblage | Nom | Poids (kg) | Surface supérieure totale (m2) | Surface nette (m2) | Longueur (mm) = Length (mm) | OuterSurfaceArea (m2) | NetVolume (m3) | NetWeight (kg)
BUTON | B0(?) | +7.542 | +7.642 | B0(?) | BUTON | 50.7 | 0.4 | 1.7 | 4331.9 | 1.67211 | 0.00662235 | 51.9854
LISSE ACROTERE | L0 | +10.205 | +10.305 | L0(?) | LISSE ACROTERE | 179.4 | 1.5 | 6.1 | 15340 | 5.92124 | 0.0235622 | 184.964
LISSE ACROTERE | L0 | +11.020 | +11.120 | L0(?) | LISSE ACROTERE | 179.4 | 1.5 | 6.1 | 15340 | 5.92124 | 0.0235622 | 184.964
LISSE ACROTERE | L0 | +11.820 | +11.920 | L0(?) | LISSE ACROTERE | 179.4 | 1.5 | 6.1 | 15340 | 5.92124 | 0.0235622 | 184.964
LISSE CHASSIS | L0 | +4.900 | +5.000 | L0(?) | LISSE CHASSIS | 62.6 | 0.4 | 2.1 | 5350 | 2.0651 | 0.0082176 | 64.5082
LISSE CHASSIS | L0 | +2.800 | +2.900 | L0(?) | LISSE CHASSIS | 62.6 | 0.4 | 2.1 | 5350 | 2.0651 | 0.0082176 | 64.5082
LISSE CHASSIS | L0 | +1.000 | +1.100 | L0(?) | LISSE CHASSIS | 62.6 | 0.4 | 2.1 | 5350 | 2.0651 | 0.0082176 | 64.5082
LISSE CHASSIS | L0 | +7.100 | +7.200 | L0(?) | LISSE CHASSIS | 59.7 | 0.4 | 1.9 | 5100 | 1.9686 | 0.0078336 | 61.4938
LISSE CHASSIS | L0 | +4.900 | +5.000 | L0(?) | LISSE CHASSIS | 59.7 | 0.4 | 1.9 | 5100 | 1.9686 | 0.0078336 | 61.4938
LISSE CHASSIS | L0 | +2.800 | +2.900 | L0(?) | LISSE CHASSIS | 59.7 | 0.4 | 1.9 | 5100 | 1.9686 | 0.0078336 | 61.4938
LISSE CHASSIS | L0 | +1.000 | +1.100 | L0(?) | LISSE CHASSIS | 59.7 | 0.4 | 1.9 | 5100 | 1.9686 | 0.0078336 | 61.4938
LISSE CHASSIS | L0 | +7.100 | +7.200 | L0(?) | LISSE CHASSIS | 50.3 | 0.4 | 1.7 | 4300 | 1.6598 | 0.0066048 | 51.8477
LISSE CHASSIS | L0 | +4.900 | +5.000 | L0(?) | LISSE CHASSIS | 50.3 | 0.4 | 1.7 | 4300 | 1.6598 | 0.0066048 | 51.8477
LISSE CHASSIS | L0 | +4.900 | +5.000 | L0(?) | LISSE CHASSIS | 45.6 | 0.4 | 1.6 | 3900 | 1.5054 | 0.0059904 | 47.0246
LISSE CHASSIS | L0 | +2.800 | +2.900 | L0(?) | LISSE CHASSIS | 45.6 | 0.4 | 1.6 | 3900 | 1.5054 | 0.0059904 | 47.0246
LISSE CHASSIS | L0 | +2.800 | +2.900 | L0(?) | LISSE CHASSIS | 50.3 | 0.4 | 1.7 | 4300 | 1.6598 | 0.0066048 | 51.8477
LISSE CHASSIS | L0 | +1.000 | +1.100 | L0(?) | LISSE CHASSIS | 50.3 | 0.4 | 1.7 | 4300 | 1.6598 | 0.0066048 | 51.8477
LISSE CHASSIS | L0 | +7.100 | +7.200 | L0(?) | LISSE CHASSIS | 48.9 | 0.4 | 1.7 | 4180 | 1.61348 | 0.00642048 | 50.4008
LISSE CHASSIS | L0 | +4.900 | +5.000 | L0(?) | LISSE CHASSIS | 48.9 | 0.4 | 1.7 | 4180 | 1.61348 | 0.00642048 | 50.4008
LISSE CHASSIS | L0 | +2.800 | +2.900 | L0(?) | LISSE CHASSIS | 48.9 | 0.4 | 1.7 | 4180 | 1.61348 | 0.00642048 | 50.4008
LISSE CHASSIS | L0 | +1.000 | +1.100 | L0(?) | LISSE CHASSIS | 48.9 | 0.4 | 1.7 | 4180 | 1.61348 | 0.00642048 | 50.4008
2 x LISSE CHASSIS | L0 | +7.100 | +7.200 | L0(?) | LISSE CHASSIS | 44.4 | 0.4 | 1.5 | 3800 | 1.4668 | 0.0058368 | 45.8189
LISSE CHASSIS | L0 | +7.100 | +7.200 | L0(?) | LISSE CHASSIS | 41.9 | 0.4 | 1.5 | 3580 | 1.38188 | 0.00549888 | 43.1662
LISSE CHASSIS | L0(?) | +2.760 | +2.860 | L0(?) | LISSE CHASSIS | 41.9 | 0.4 | 1.5 | 3580 | 1.38188 | 0.00549888 | 43.1662
2 x LISSE CHASSIS | L0(?) | +2.760 | +2.860 | L0(?) | LISSE CHASSIS | 44.4 | 0.4 | 1.5 | 3800 | 1.4668 | 0.0058368 | 45.8189
MONTANT | M0(?) | +2.860 | +7.100 | M0(?) | MONTANT | 49.6 | 0 | 1.7 | 4240 | 1.63664 | 0.00651264 | 51.1242
LISSE CHASSIS | L0 | +7.100 | +7.200 | L0(?) | LISSE CHASSIS | 40.8 | 0.4 | 1.5 | 3490 | 1.34714 | 0.00536064 | 42.081
LISSE CHASSIS | L0(?) | +2.760 | +2.860 | L0(?) | LISSE CHASSIS | 40.8 | 0.4 | 1.5 | 3490 | 1.34714 | 0.00536064 | 42.081
LISSE ACROTERE | L0 | +8.450 | +8.550 | L0(?) | LISSE ACROTERE | 180.5 | 1.5 | 6.1 | 15435 | 5.95791 | 0.0237082 | 186.109
LISSE ACROTERE | L0 | +8.450 | +8.550 | L0(?) | LISSE ACROTERE | 178.4 | 1.5 | 6.1 | 15255 | 5.88843 | 0.0234317 | 183.939
2 x LISSE ACROTERE | L0 | +8.450 | +8.550 | L0(?) | LISSE ACROTERE | 181.8 | 1.6 | 6.1 | 15540 | 5.99844 | 0.0238694 | 187.375
LISSE ACROTERE | L0 | +8.450 | +8.550 | L0(?) | LISSE ACROTERE | 123.3 | 1.1 | 4.2 | 10545 | 4.07037 | 0.0161971 | 127.147
4 x LISSE ACROTERE | L0 | +8.450 | +8.550 | L0(?) | LISSE ACROTERE | 43.4 | 0.4 | 1.5 | 3708 | 1.43129 | 0.00569549 | 44.7096
3 x LISSE ACROTERE | L0 | +8.450 | +8.550 | L0(?) | LISSE ACROTERE | 43.2 | 0.4 | 1.5 | 3690 | 1.42434 | 0.00566784 | 44.4925
LISSE ACROTERE | L0 | +8.450 | +8.550 | L0(?) | LISSE ACROTERE | 43.8 | 0.4 | 1.5 | 3745 | 1.44557 | 0.00575232 | 45.1557
3 x LISSE ACROTERE | L0 | +8.450 | +8.550 | L0(?) | LISSE ACROTERE | 42.9 | 0.4 | 1.5 | 3670 | 1.41662 | 0.00563712 | 44.2514
LISSE ACROTERE | L0 | +8.450 | +8.550 | L0(?) | LISSE ACROTERE | 42.5 | 0.4 | 1.5 | 3630 | 1.40118 | 0.00557568 | 43.7691
LISSE ACROTERE | L0 | +8.450 | +8.550 | L0(?) | LISSE ACROTERE | 178.4 | 1.5 | 6.1 | 15245 | 5.88457 | 0.0234163 | 183.818
LISSE ACROTERE | L0 | +8.450 | +8.550 | L0(?) | LISSE ACROTERE | 145.7 | 1.3 | 5 | 12460 | 4.80956 | 0.0191386 | 150.238

# IfcBeam: TUBE-C-40*40*4 (8)
In: Undefined
Description: TUBE-C-40*40*4; Material: STEEL/S235-E24
Tekla Commun - Repère de pièce: B0; Repère d'assemblage: B0(?); Phase: 1; Classe: 2; Matériau: S235-E24; Profil: TUBE-C-40*40*4; Nom: BUTON
Tekla Quantités - Poids: 16 kg; Volume: 0 m3; Surface supérieure totale: 0 m2; Surface par tonne: 34.8 m2; Surface nette: 0.6 m2; Hauteur: 40 mm; Largeur: 40 mm; Longueur: 3800 mm
Pset_BeamCommon - LoadBearing: yes; Reference: B0
BaseQuantities - Length: 3800 mm; OuterSurfaceArea: 0.5548 m2; NetVolume: 0.0021888 m3; NetWeight: 17.1821 kg
Name | Niveau bas | Niveau haut
4 x BUTON | +9.844 | +9.898
4 x BUTON | +10.247 | +10.301

# IfcBeam: TUBE-C-60*60*3 (26)
In: Undefined
Description: TUBE-C-60*60*3; Material: STEEL/S235-E24
Tekla Commun - Niveau bas: +7.985; Niveau haut: +8.045; Repère de pièce: S0; Repère d'assemblage: S0(?); Phase: 1; Classe: 2; Matériau: S235-E24; Profil: TUBE-C-60*60*3; Nom: SOLIVE
Tekla Quantités - Volume: 0 m3; Surface par tonne: 44.1 m2; Hauteur: 60 mm; Largeur: 60 mm
Pset_BeamCommon - LoadBearing: yes; Reference: S0
Name | Poids (kg) | Surface supérieure totale (m2) | Surface nette (m2) | Longueur (mm) | Length (mm) | OuterSurfaceArea (m2) | NetVolume (m3) | NetWeight (kg)
24 x SOLIVE | 6.2 | 0.1 | 0.3 | 1195 | 1194.99 | 0.273653 | 0.000817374 | 6.41639
SOLIVE | 5.5 | 0.1 | 0.3 | 1051.5 | 1051.49 | 0.240792 | 0.00071922 | 5.64588
SOLIVE | 4.2 | 0 | 0.2 | 826.5 | 826.5 | 0.189268 | 0.000565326 | 4.43781

# IfcBeam: TUBE-C-80*80*4 (3)
In: Undefined
Description: TUBE-C-80*80*4; Material: STEEL/S235-E24
Pset_BeamCommon - LoadBearing: yes
Tekla Commun - Phase: 1; Classe: 2; Matériau: S235-E24; Profil: TUBE-C-80*80*4
Tekla Quantités - Volume: 0 m3; Surface par tonne: 33.2 m2; Hauteur: 80 mm; Largeur: 80 mm
Name | Reference = Repère de pièce | Niveau bas | Niveau haut | Repère d'assemblage | Nom | Poids (kg) | Surface supérieure totale (m2) | Surface nette (m2) | Longueur (mm) | Length (mm) | OuterSurfaceArea (m2) | NetVolume (m3) | NetWeight (kg)
LISSE ACROTERE | L0 | +8.470 | +8.550 | L0(?) | LISSE ACROTERE | 36 | 0.4 | 1.3 | 3900 | 3900 | 1.1934 | 0.0047424 | 37.2278
RAMASSE PANNE | RP0(?) | +7.302 | +7.611 | RP0(?) | RAMASSE PANNE | 67.2 | 0 | 2.3 | 7286.1 | 7286.11 | 2.22955 | 0.00885685 | 69.5263
RAMASSE PANNE | RP0(?) | +7.531 | +7.843 | RP0(?) | RAMASSE PANNE | 68 | 0 | 2.4 | 7376.2 | 7376.15 | 2.2571 | 0.00896634 | 70.3858

# IfcBeam: UPF-100*50*4 (42)
In: Undefined
Description: UPF-100*50*4; Material: STEEL/S235-E24
Tekla Commun - Phase: 1; Classe: 2; Matériau: S235-E24; Profil: UPF-100*50*4
Tekla Quantités - Volume: 0 m3; Hauteur: 100 mm; Largeur: 50 mm
Pset_BeamCommon - LoadBearing: yes
Name | Niveau bas | Niveau haut | Repère de pièce = Reference | Repère d'assemblage | Nom | Poids (kg) | Surface supérieure totale (m2) | Surface par tonne (m2) | Surface nette (m2) | Longueur (mm) | Length (mm) | OuterSurfaceArea (m2) | NetVolume (m3) | NetWeight (kg)
7 x LISSE CONTREBARDAGE | +8.023 | +8.197 | L0(?) | L0(?) | LISSE CONTREBARDAGE | 23.2 | 0 | 66.9 | 1.6 | 3962.7 | 3962.74 | 1.5545 | 0.00304252 | 23.8837
8 x LISSE CONTREBARDAGE | +8.147 | +8.316 | L0(?) | L0(?) | LISSE CONTREBARDAGE | 22.3 | 0 | 66.9 | 1.5 | 3801.9 | 3801.88 | 1.49187 | 0.00291984 | 22.9208
8 x LISSE CONTREBARDAGE | +8.266 | +8.436 | L0(?) | L0(?) | LISSE CONTREBARDAGE | 22.3 | 0 | 66.9 | 1.5 | 3801.9 | 3801.88 | 1.49187 | 0.00291984 | 22.9208
BAIONNETTE | +7.220 | +8.445 | B0(?) | B0(?) | BAIONNETTE | 7.2 | 0 | 63.9 | 0.5 | 1225 | 1225 | 0.459295 | 0.000895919 | 7.03296
BAIONNETTE | +7.690 | +8.445 | B0(?) | B0(?) | BAIONNETTE | 4.4 | 0 | 62.1 | 0.3 | 755 | 754.999 | 0.275055 | 0.000534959 | 4.19943
BAIONNETTE | +7.775 | +8.445 | B0(?) | B0(?) | BAIONNETTE | 3.9 | 0 | 61.5 | 0.2 | 670 | 669.999 | 0.241735 | 0.000469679 | 3.68698
BAIONNETTE | +7.655 | +8.445 | B0(?) | B0(?) | BAIONNETTE | 4.6 | 0 | 62.3 | 0.3 | 790 | 789.999 | 0.288775 | 0.000561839 | 4.41044
BAIONNETTE | +7.535 | +8.445 | B0(?) | B0(?) | BAIONNETTE | 5.3 | 0 | 62.9 | 0.3 | 910 | 909.999 | 0.335815 | 0.000653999 | 5.13389
LISSE | +1.600 | +1.650 | L0 | L0(?) | LISSE | 17.7 | 0.4 | 66.9 | 1.3 | 3018 | 3018 | 1.18459 | 0.00231782 | 18.1949 | Tekla Commun - Finition: GALVA
LISSE | +0.100 | +0.150 | L0 | L0(?) | LISSE | 17.7 | 0.4 | 66.9 | 1.3 | 3018 | 3018 | 1.18459 | 0.00231782 | 18.1949 | Tekla Commun - Finition: GALVA
2 x LISSE | +1.600 | +1.650 | L0 | L0(?) | LISSE | 6.7 | 0.1 | 67.1 | 0.3 | 1140 | 1140 | 0.448416 | 0.00087552 | 6.87283 | Tekla Commun - Finition: GALVA
2 x LISSE | +1.600 | +1.650 | L0 | L0(?) | LISSE | 10.3 | 0.2 | 66.9 | 0.6 | 1750 | 1750 | 0.687536 | 0.001344 | 10.5504 | Tekla Commun - Finition: GALVA
2 x LISSE | +0.100 | +0.150 | L0 | L0(?) | LISSE | 6.7 | 0.1 | 67.1 | 0.3 | 1140 | 1140 | 0.448416 | 0.00087552 | 6.87283 | Tekla Commun - Finition: GALVA
2 x LISSE | +0.100 | +0.150 | L0 | L0(?) | LISSE | 10.3 | 0.2 | 66.9 | 0.6 | 1750 | 1750 | 0.687536 | 0.001344 | 10.5504 | Tekla Commun - Finition: GALVA
LISSE CONTREBARDAGE | +8.023 | +8.197 | L0(?) | L0(?) | LISSE CONTREBARDAGE | 23.2 | 0 | 66.9 | 1.6 | 3963.3 | 3963.29 | 1.55466 | 0.00304284 | 23.8863
LISSE CONTREBARDAGE | +8.147 | +8.316 | L0(?) | L0(?) | LISSE CONTREBARDAGE | 22.3 | 0 | 66.9 | 1.5 | 3802.3 | 3802.32 | 1.49204 | 0.00292018 | 22.9234
LISSE CONTREBARDAGE | +8.266 | +8.436 | L0(?) | L0(?) | LISSE CONTREBARDAGE | 22.3 | 0 | 66.9 | 1.5 | 3802.3 | 3802.32 | 1.49204 | 0.00292018 | 22.9234
LISSE CONTREBARDAGE | +8.028 | +8.197 | L0(?) | L0(?) | LISSE CONTREBARDAGE | 22.3 | 0 | 66.9 | 1.5 | 3791.9 | 3791.87 | 1.48795 | 0.00291215 | 22.8604

# IfcBeam: UPF-150*50*5 (6)
In: Undefined
Description: UPF-150*50*5; Material: STEEL/S235-E24
Pset_BeamCommon - LoadBearing: yes
Tekla Commun - Phase: 1; Classe: 2; Matériau: S235-E24; Profil: UPF-150*50*5
Tekla Quantités - Volume: 0 m3; Surface supérieure totale: 0 m2; Hauteur: 150 mm; Largeur: 50 mm
Name | Reference = Repère de pièce | Niveau bas | Niveau haut | Repère d'assemblage | Finition | Nom | Poids (kg) | Surface par tonne (m2) | Surface nette (m2) | Longueur (mm) = Length (mm) | OuterSurfaceArea (m2) | NetVolume (m3) | NetWeight (kg)
LINTEAU | L0 | +2.040 | +2.090 | L0(?) | GALVA | LINTEAU | 10.5 | 53.7 | 0.6 | 1130 | 0.5561 | 0.001356 | 10.6446
LINTEAU | L0 | +2.040 | +2.090 | L0(?) | GALVA | LINTEAU | 10.3 | 53.7 | 0.6 | 1130 | 0.5561 | 0.001356 | 10.6446
2 x MONTANT | M0 | -0.090 | +2.886 | M0(?) | GALVA | MONTANT | 27.3 | 53.5 | 1.5 | 2976.3 | 1.46079 | 0.00357157 | 28.0368
MONTANT | M0 | -0.090 | +2.100 | M0(?) |  | MONTANT | 20.1 | 53.6 | 1.1 | 2190 | 1.0755 | 0.002628 | 20.6298
LINTEAU | L0 | +2.100 | +2.150 | L0(?) |  | LINTEAU | 32 | 53.5 | 1.7 | 3490 | 1.7125 | 0.004188 | 32.8758

# IfcBeam: UPF-150*70*5 (3)
In: Undefined
Description: UPF-150*70*5; Material: STEEL/S235-E24
Pset_BeamCommon - LoadBearing: yes
Tekla Commun - Niveau bas: +7.950; Niveau haut: +8.100; Repère d'assemblage: L0(?); Phase: 1; Classe: 2; Matériau: S235-E24; Profil: UPF-150*70*5; Nom: LONGERON
Tekla Quantités - Volume: 0 m3; Surface supérieure totale: 1.1 m2; Surface par tonne: 53.1 m2; Hauteur: 150 mm; Largeur: 70 mm
Name | Reference = Repère de pièce | Poids (kg) | Surface nette (m2) | Longueur (mm) = Length (mm) | OuterSurfaceArea (m2) | NetVolume (m3) | NetWeight (kg)
LONGERON | L0(?) | 161.5 | 8.6 | 15040 | 8.5756 | 0.021056 | 165.29
LONGERON | L0 | 165.7 | 8.8 | 15430 | 8.7979 | 0.021602 | 169.576
LONGERON | L0 | 164.7 | 8.8 | 15340 | 8.7466 | 0.021476 | 168.587

# IfcBeam: UPF-300*82.5*6 (3)
In: Undefined
Description: UPF-300*82.5*6; Material: STEEL/S235-E24
Tekla Commun - Niveau bas: +7.940; Niveau haut: +8.240; Repère de pièce: L0; Repère d'assemblage: L0(?); Phase: 1; Classe: 2; Matériau: S235-E24; Profil: UPF-300*82.5*6; Nom: LONGERON
Tekla Quantités - Poids: 247.3 kg; Volume: 0 m3; Surface supérieure totale: 1.3 m2; Surface nette: 14.2 m2; Hauteur: 300 mm; Largeur: 82.5 mm; Longueur: 15430 mm
Pset_BeamCommon - LoadBearing: yes; Reference: L0
BaseQuantities - Length: 15430 mm
Name | Surface par tonne (m2) | OuterSurfaceArea (m2) | NetVolume (m3) | NetWeight (kg)
2 x LONGERON | 57.3 | 14.1702 | 0.0419387 | 329.219
LONGERON | 57.1 | 14.1142 | 0.0417709 | 327.901

# IfcBeam: UPN140 (7)
In: Undefined
Description: UPN140; Material: STEEL/S275-E28
Tekla Commun - Niveau haut: +8.270; Repère de pièce: M0; Repère d'assemblage: M0(?); Phase: 1; Classe: 2; Matériau: S275-E28; Profil: UPN140; Nom: MONTANT
Tekla Quantités - Volume: 0 m3; Surface supérieure totale: 0 m2; Surface par tonne: 30.4 m2; Hauteur: 140 mm; Largeur: 60 mm
Pset_BeamCommon - LoadBearing: yes; Reference: M0
Name | Niveau bas | Poids (kg) | Surface nette (m2) | Longueur (mm) | Length (mm) | OuterSurfaceArea (m2) | NetVolume (m3) | NetWeight (kg)
2 x MONTANT | +7.940 | 5.3 | 0.2 | 330 | 329.994 | 0.160707 | 0.000663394 | 5.20765
5 x MONTANT | +5.260 | 48.2 | 1.5 | 3010 | 3009.99 | 1.46587 | 0.00605105 | 47.5008

# IfcBeam: UPN180, RAMASSE PANNE
In: Undefined
Description: UPN180; Material: STEEL/S275-E28
Pset_BeamCommon - LoadBearing: yes; Reference: 0(?)
Tekla Commun - Niveau bas: +7.861; Niveau haut: +8.048; Repère de pièce: 0(?); Repère d'assemblage: 0(?); Phase: 1; Classe: 2; Matériau: S275-E28; Profil: UPN180; Nom: RAMASSE PANNE
Tekla Quantités - Poids: 4.9 kg; Volume: 0 m3; Surface supérieure totale: 0 m2; Surface par tonne: 27.5 m2; Surface nette: 0.1 m2; Hauteur: 180 mm; Largeur: 70 mm; Longueur: 225.1 mm
BaseQuantities - Length: 225.065 mm; OuterSurfaceArea: 0.135489 m2; NetVolume: 0.000614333 m3; NetWeight: 4.82251 kg

# IfcBeam: UPN260 (2)
In: Undefined
Description: UPN260; Material: STEEL/S275-E28
Tekla Commun - Niveau bas: +5.000; Niveau haut: +5.260; Repère de pièce: TB0; Repère d'assemblage: TB0(?); Phase: 1; Classe: 2; Matériau: S275-E28; Profil: UPN260; Nom: TRAVERSE BASSE
Tekla Quantités - Poids: 591.5 kg; Volume: 0.1 m3; Surface supérieure totale: 1.5 m2; Surface par tonne: 21.9 m2; Surface nette: 13.2 m2; Hauteur: 260 mm; Largeur: 90 mm; Longueur: 15600 mm
Pset_BeamCommon - LoadBearing: yes; Reference: TB0
BaseQuantities - Length: 15600 mm; OuterSurfaceArea: 12.9792 m2; NetVolume: 0.0745056 m3; NetWeight: 584.869 kg

# IfcBeam: UPN280 (2)
In: Undefined
Description: UPN280; Material: STEEL/S275-E28
Tekla Commun - Niveau bas: +8.270; Niveau haut: +8.550; Repère de pièce: TH0; Repère d'assemblage: TH0(?); Phase: 1; Classe: 2; Matériau: S275-E28; Profil: UPN280; Nom: TRAVERSE HAUTE
Tekla Quantités - Poids: 653.9 kg; Volume: 0.1 m3; Surface supérieure totale: 1.5 m2; Surface par tonne: 21.3 m2; Surface nette: 14.2 m2; Hauteur: 280 mm; Largeur: 95 mm; Longueur: 15600 mm
Pset_BeamCommon - LoadBearing: yes; Reference: TH0
BaseQuantities - Length: 15600 mm; OuterSurfaceArea: 13.8996 m2; NetVolume: 0.0823992 m3; NetWeight: 646.834 kg

# IfcColumn: HEA100 (4)
In: Undefined
Description: HEA100; Material: STEEL/S275-E28
Tekla Commun - Niveau haut: +8.445; Repère de pièce: 0(?); Repère d'assemblage: 0(?); Phase: 1; Classe: 2; Matériau: S275-E28; Profil: HEA100; Nom: BAIONNETTE
Tekla Quantités - Volume: 0 m3; Surface supérieure totale: 0 m2; Surface par tonne: 33.6 m2; Hauteur: 96 mm; Largeur: 100 mm
Pset_ColumnCommon - LoadBearing: yes; Reference: 0(?)
Name | Niveau bas | Poids (kg) | Surface nette (m2) | Longueur (mm) | Length (mm) | OuterSurfaceArea (m2) | NetVolume (m3) | NetWeight (kg)
BAIONNETTE | +7.572 | 14.6 | 0.5 | 872.7 | 872.679 | 0.489573 | 0.00174536 | 13.7011
BAIONNETTE | +7.931 | 8.6 | 0.3 | 514.4 | 514.436 | 0.288599 | 0.00102887 | 8.07665
BAIONNETTE | +7.811 | 10.6 | 0.3 | 633.8 | 633.84 | 0.355584 | 0.00126768 | 9.95128
BAIONNETTE | +7.692 | 12.6 | 0.3 | 753.3 | 753.307 | 0.422605 | 0.00150661 | 11.8269

# IfcColumn: HEA140 (17)
In: Undefined
Description: HEA140; Material: STEEL/S275-E28
Tekla Commun - Phase: 1; Classe: 2; Matériau: S275-E28; Profil: HEA140
Tekla Quantités - Volume: 0 m3; Surface supérieure totale: 0 m2; Surface par tonne: 32.2 m2; Hauteur: 133 mm; Largeur: 140 mm
Pset_ColumnCommon - LoadBearing: yes
Name | Niveau bas | Niveau haut | Repère de pièce = Reference | Repère d'assemblage | Nom | Poids (kg) | Surface nette (m2) | Longueur (mm) | Length (mm) | OuterSurfaceArea (m2) | NetVolume (m3) | NetWeight (kg)
MONTANT | +8.000 | +8.550 | 0 | 0(?) | MONTANT | 13.6 | 0.5 | 550 | 550 | 0.4367 | 0.0016599 | 13.0302
4 x MONTANT | +7.250 | +10.423 | M0 | M0(?) | MONTANT | 78.3 | 2.6 | 3173 | 3173 | 2.51936 | 0.00957611 | 75.1725
MONTANT | +8.450 | +10.423 | M0 | M0(?) | MONTANT | 48.7 | 1.6 | 1973 | 1973 | 1.56656 | 0.00595451 | 46.7429
4 x MONTANT | +7.250 | +11.236 | M0 | M0(?) | MONTANT | 98.3 | 3.3 | 3986 | 3986 | 3.16488 | 0.0120297 | 94.4335
MONTANT | +8.550 | +11.236 | M0 | M0(?) | MONTANT | 66.2 | 2.2 | 2686 | 2686 | 2.13268 | 0.00810635 | 63.6348
4 x MONTANT | +7.250 | +12.037 | M0 | M0(?) | MONTANT | 118.1 | 4 | 4787 | 4787 | 3.80088 | 0.0144472 | 113.41
MONTANT | +8.550 | +12.037 | M0 | M0(?) | MONTANT | 86 | 2.8 | 3487 | 3487 | 2.76868 | 0.0105238 | 82.6116
BAIONNETTE | +8.051 | +8.445 | 0(?) | 0(?) | BAIONNETTE | 9.7 | 0.3 | 393.5 | 393.523 | 0.312457 | 0.00118135 | 9.27356

# IfcColumn: IPE160 (2)
In: Undefined
Description: IPE160; Material: STEEL/S275-E28
Tekla Commun - Niveau bas: -0.230; Niveau haut: +2.824; Repère de pièce: PT0; Repère d'assemblage: PT0(?); Finition: GALVA; Phase: 1; Classe: 2; Matériau: S275-E28; Profil: IPE160; Nom: POTEAU
Tekla Quantités - Poids: 48.2 kg; Volume: 0 m3; Surface supérieure totale: 0 m2; Surface par tonne: 39.5 m2; Surface nette: 1.9 m2; Hauteur: 160 mm; Largeur: 82 mm; Longueur: 3054 mm
Pset_ColumnCommon - LoadBearing: yes; Reference: PT0
BaseQuantities - OuterSurfaceArea: 1.90262 m2
Name | Length (mm) | NetVolume (m3) | NetWeight (kg)
POTEAU | 3053.97 | 0.00591535 | 46.4355
POTEAU | 3053.96 | 0.00591533 | 46.4353

# IfcColumn: IPE270 (3)
In: Undefined
Description: IPE270; Material: STEEL/S275-E28
Pset_ColumnCommon - LoadBearing: yes; Reference: PT0(?)
Tekla Commun - Niveau bas: -0.230; Repère de pièce: PT0(?); Repère d'assemblage: PT0(?); Phase: 1; Classe: 2; Matériau: S275-E28; Profil: IPE270; Nom: POTEAU
Tekla Quantités - Volume: 0 m3; Surface supérieure totale: 0 m2; Surface par tonne: 28.9 m2; Hauteur: 270 mm; Largeur: 135 mm
Name | Niveau haut | Poids (kg) | Surface nette (m2) | Longueur (mm) = Length (mm) | OuterSurfaceArea (m2) | NetVolume (m3) | NetWeight (kg)
POTEAU | +7.925 | 293.8 | 8.8 | 8155 | 8.48935 | 0.0358931 | 281.761
POTEAU | +7.805 | 289.5 | 8.6 | 8035 | 8.36444 | 0.0353649 | 277.615
POTEAU | +7.685 | 285.2 | 8.6 | 7915 | 8.23952 | 0.0348368 | 273.469

# IfcColumn: IPE400 (2)
In: Undefined
Description: IPE400; Material: STEEL/S275-E28
Pset_ColumnCommon - LoadBearing: yes; Reference: PT0(?)
Tekla Commun - Niveau bas: -0.230; Repère de pièce: PT0(?); Repère d'assemblage: PT0(?); Phase: 1; Classe: 2; Matériau: S275-E28; Profil: IPE400; Nom: POTEAU
Tekla Quantités - Volume: 0.1 m3; Surface supérieure totale: 0 m2; Surface par tonne: 22.1 m2; Hauteur: 400 mm; Largeur: 180 mm
Name | Niveau haut | Poids (kg) | Surface nette (m2) | Longueur (mm) = Length (mm) | OuterSurfaceArea (m2) | NetVolume (m3) | NetWeight (kg)
POTEAU | +7.370 | 504.1 | 11.4 | 7600 | 11.1492 | 0.0613153 | 481.325
POTEAU | +7.840 | 535.3 | 12.1 | 8070 | 11.8387 | 0.0651071 | 511.091

# IfcColumn: IPE500 (4)
In: Undefined
Description: IPE500; Material: STEEL/S275-E28
Tekla Commun - Niveau bas: -0.235; Repère de pièce: PT0(?); Repère d'assemblage: PT0(?); Phase: 1; Classe: 2; Matériau: S275-E28; Profil: IPE500; Nom: POTEAU
Tekla Quantités - Volume: 0.1 m3; Surface supérieure totale: 0 m2; Surface par tonne: 19.2 m2; Hauteur: 500 mm; Largeur: 200 mm
Pset_ColumnCommon - LoadBearing: yes; Reference: PT0(?)
Name | Niveau haut | Poids (kg) | Surface nette (m2) | Longueur (mm) | Length (mm) | OuterSurfaceArea (m2) | NetVolume (m3) | NetWeight (kg)
3 x POTEAU | +8.046 | 754 | 14.7 | 8280.7 | 8280.65 | 14.4415 | 0.0924369 | 725.63
POTEAU | +8.440 | 789.9 | 15.5 | 8675 | 8675 | 15.1292 | 0.096931 | 760.908

# IfcColumn: IPE600 (2)
In: Undefined
Description: IPE600; Material: STEEL/S275-E28
Pset_ColumnCommon - LoadBearing: yes; Reference: PT0
Tekla Commun - Niveau bas: -0.235; Niveau haut: +8.540; Repère de pièce: PT0; Repère d'assemblage: PT0(?); Phase: 1; Classe: 2; Matériau: S275-E28; Profil: IPE600; Nom: POTEAU
Tekla Quantités - Poids: 1074.6 kg; Volume: 0.1 m3; Surface supérieure totale: 0 m2; Surface par tonne: 16.5 m2; Surface nette: 18.1 m2; Hauteur: 600 mm; Largeur: 220 mm; Longueur: 8775 mm
BaseQuantities - Length: 8775 mm; OuterSurfaceArea: 17.6816 m2; NetVolume: 0.132538 m3; NetWeight: 1040.42 kg

# IfcColumn: L100*10 (6)
In: Undefined
Description: L100*10; Material: STEEL/S235-E24
Tekla Commun - Repère d'assemblage: A0(?); Phase: 1; Classe: 2; Matériau: S235-E24; Profil: L100*10; Nom: ATTACHE
Tekla Quantités - Volume: 0 m3; Surface supérieure totale: 0 m2; Surface par tonne: 25.9 m2; Surface nette: 0.1 m2; Hauteur: 100 mm; Largeur: 100 mm
Pset_ColumnCommon - LoadBearing: yes
Name | Niveau bas | Niveau haut | Repère de pièce = Reference | Poids (kg) | Longueur (mm) = Length (mm) | OuterSurfaceArea (m2) | NetVolume (m3) | NetWeight (kg)
2 x ATTACHE | +7.203 | +7.483 | A0(?) | 4.2 | 280 | 0.1092 | 0.000532 | 4.1762
3 x ATTACHE | +7.970 | +8.210 | A0 | 3.6 | 240 | 0.0936 | 0.000456 | 3.5796
ATTACHE | +7.240 | +7.420 | A0 | 2.7 | 180 | 0.0702 | 0.000342 | 2.6847

# IfcColumn: L80*8, ATTACHE
In: Undefined
Description: L80*8; Material: STEEL/S235-E24
Pset_ColumnCommon - LoadBearing: yes; Reference: A0
Tekla Commun - Niveau bas: +3.255; Niveau haut: +3.375; Repère de pièce: A0; Repère d'assemblage: A0(?); Phase: 1; Classe: 2; Matériau: S235-E24; Profil: L80*8; Nom: ATTACHE
Tekla Quantités - Poids: 1.2 kg; Volume: 0 m3; Surface supérieure totale: 0 m2; Surface par tonne: 32.2 m2; Surface nette: 0 m2; Hauteur: 80 mm; Largeur: 80 mm; Longueur: 120 mm
BaseQuantities - Length: 120 mm; OuterSurfaceArea: 0.03732 m2; NetVolume: 0.00014592 m3; NetWeight: 1.14547 kg

# IfcColumn: TUBE-C-100*100*4 (15)
In: Undefined
Description: TUBE-C-100*100*4; Material: STEEL/S235-E24
Pset_ColumnCommon - LoadBearing: yes; Reference: M0
Tekla Commun - Repère de pièce: M0; Repère d'assemblage: M0(?); Phase: 1; Classe: 2; Matériau: S235-E24; Profil: TUBE-C-100*100*4; Nom: MONTANT
Tekla Quantités - Volume: 0 m3; Surface supérieure totale: 0 m2; Surface par tonne: 33 m2; Hauteur: 100 mm; Largeur: 100 mm
Name | Niveau bas | Niveau haut | Poids (kg) | Surface nette (m2) | Longueur (mm) = Length (mm) | OuterSurfaceArea (m2) | NetVolume (m3) | NetWeight (kg)
2 x MONTANT | +8.550 | +10.205 | 19.4 | 0.6 | 1655 | 0.63883 | 0.00254208 | 19.9553
2 x MONTANT | +8.550 | +11.020 | 28.9 | 0.9 | 2470 | 0.95342 | 0.00379392 | 29.7823
2 x MONTANT | +8.550 | +11.820 | 38.2 | 1.3 | 3270 | 1.26222 | 0.00502272 | 39.4284
3 x MONTANT | +2.900 | +4.900 | 23.4 | 0.9 | 2000 | 0.772 | 0.003072 | 24.1152
3 x MONTANT | +5.000 | +7.100 | 24.6 | 0.9 | 2100 | 0.8106 | 0.0032256 | 25.321
3 x MONTANT | +1.100 | +2.800 | 19.9 | 0.6 | 1700 | 0.6562 | 0.0026112 | 20.4979

# IfcColumn: TUBE-C-80*80*4 (3)
In: Undefined
Description: TUBE-C-80*80*4; Material: STEEL/S235-E24
Tekla Commun - Niveau bas: +5.000; Repère de pièce: M0; Repère d'assemblage: M0(?); Phase: 1; Classe: 2; Matériau: S235-E24; Profil: TUBE-C-80*80*4; Nom: MONTANT BARDAGE
Tekla Quantités - Volume: 0 m3; Surface supérieure totale: 0 m2; Surface par tonne: 33.2 m2; Hauteur: 80 mm; Largeur: 80 mm
Pset_ColumnCommon - LoadBearing: yes; Reference: M0
Name | Niveau haut | Poids (kg) | Surface nette (m2) | Longueur (mm) | Length (mm) | OuterSurfaceArea (m2) | NetVolume (m3) | NetWeight (kg)
2 x MONTANT BARDAGE | +8.550 | 32.7 | 1.1 | 3550 | 3550 | 1.0863 | 0.0043168 | 33.8869
MONTANT BARDAGE | +10.340 | 49.3 | 1.7 | 5340.3 | 5340.34 | 1.63414 | 0.0064684 | 50.777

# IfcColumn: TUBE-R-100*50*3 (9)
In: Undefined
Description: TUBE-R-100*50*3; Material: STEEL/S235-E24
Tekla Commun - Niveau bas: +8.240; Repère de pièce: S0; Repère d'assemblage: S0(?); Phase: 1; Classe: 2; Matériau: S235-E24; Profil: TUBE-R-100*50*3; Nom: SUSPENTE
Tekla Quantités - Volume: 0 m3; Surface supérieure totale: 0 m2; Surface par tonne: 42.8 m2; Hauteur: 100 mm; Largeur: 50 mm
Pset_ColumnCommon - LoadBearing: yes; Reference: S0
Name | Niveau haut | Poids (kg) | Surface nette (m2) | Longueur (mm) | Length (mm) | OuterSurfaceArea (m2) | NetVolume (m3) | NetWeight (kg)
3 x SUSPENTE | +9.775 | 10.5 | 0.5 | 1535.2 | 1535.25 | 0.443686 | 0.00131578 | 10.3289
3 x SUSPENTE | +10.512 | 15.3 | 0.6 | 2272.1 | 2272.06 | 0.656626 | 0.00195187 | 15.3222
3 x SUSPENTE | +11.261 | 20.4 | 0.9 | 3021.5 | 3021.46 | 0.873202 | 0.00259924 | 20.404

# IfcColumn: UPF-100*50*4 (5)
In: Undefined
Description: UPF-100*50*4; Material: STEEL/S235-E24
Tekla Commun - Niveau haut: +8.445; Repère de pièce: B0(?); Repère d'assemblage: B0(?); Phase: 1; Classe: 2; Matériau: S235-E24; Profil: UPF-100*50*4; Nom: BAIONNETTE
Tekla Quantités - Volume: 0 m3; Surface supérieure totale: 0 m2; Hauteur: 100 mm; Largeur: 50 mm
Pset_ColumnCommon - LoadBearing: yes; Reference: B0(?)
Name | Niveau bas | Poids (kg) | Surface par tonne (m2) | Surface nette (m2) | Longueur (mm) | Length (mm) | OuterSurfaceArea (m2) | NetVolume (m3) | NetWeight (kg)
BAIONNETTE | +7.220 | 7.2 | 63.9 | 0.5 | 1225 | 1225 | 0.459295 | 0.00089592 | 7.03297
BAIONNETTE | +7.690 | 4.4 | 62.1 | 0.3 | 755 | 754.999 | 0.275055 | 0.000534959 | 4.19943
BAIONNETTE | +7.775 | 3.9 | 61.5 | 0.2 | 670 | 669.999 | 0.241735 | 0.000469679 | 3.68698
BAIONNETTE | +7.655 | 4.6 | 62.3 | 0.3 | 790 | 789.999 | 0.288775 | 0.000561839 | 4.41044
BAIONNETTE | +7.535 | 5.3 | 62.9 | 0.3 | 910 | 909.999 | 0.335815 | 0.000653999 | 5.13389

# IfcColumn: UPF-150*50*5 (2)
In: Undefined
Description: UPF-150*50*5; Material: STEEL/S235-E24
Pset_ColumnCommon - LoadBearing: yes; Reference: M0
Tekla Commun - Niveau bas: -0.090; Niveau haut: +2.945; Repère de pièce: M0; Repère d'assemblage: M0(?); Finition: GALVA; Phase: 1; Classe: 2; Matériau: S235-E24; Profil: UPF-150*50*5; Nom: MONTANT
Tekla Quantités - Poids: 27.7 kg; Volume: 0 m3; Surface supérieure totale: 0 m2; Surface par tonne: 53.5 m2; Surface nette: 1.5 m2; Hauteur: 150 mm; Largeur: 50 mm; Longueur: 3035.5 mm
BaseQuantities - Length: 3035.49 mm; OuterSurfaceArea: 1.48979 m2; NetVolume: 0.00364259 m3; NetWeight: 28.5944 kg

# IfcColumn: UPN140 (7)
In: Undefined
Description: UPN140; Material: STEEL/S275-E28
Pset_ColumnCommon - LoadBearing: yes; Reference: M0
Tekla Commun - Niveau haut: +8.270; Repère de pièce: M0; Repère d'assemblage: M0(?); Phase: 1; Classe: 2; Matériau: S275-E28; Profil: UPN140; Nom: MONTANT
Tekla Quantités - Volume: 0 m3; Surface supérieure totale: 0 m2; Surface par tonne: 30.4 m2; Hauteur: 140 mm; Largeur: 60 mm
Name | Niveau bas | Poids (kg) | Surface nette (m2) | Longueur (mm) | Length (mm) | OuterSurfaceArea (m2) | NetVolume (m3) | NetWeight (kg)
2 x MONTANT | +7.940 | 5.3 | 0.2 | 330 | 329.994 | 0.160707 | 0.000663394 | 5.20765
5 x MONTANT | +5.260 | 48.2 | 1.5 | 3010 | 3009.99 | 1.46587 | 0.00605105 | 47.5008

# IfcDiscreteAccessory: BAIONNETTE (2)
In: Undefined
Description: HEA100; Material: STEEL/S275-E28
Tekla Commun - Niveau bas: +8.053; Niveau haut: +8.445; Repère de pièce: 211(?); Repère d'assemblage: PT0(?); Phase: 1; Classe: 2; Matériau: S275-E28; Profil: HEA100; Nom: BAIONNETTE
Tekla Quantités - Poids: 6.5 kg; Volume: 0 m3; Surface supérieure totale: 0 m2; Surface par tonne: 33.6 m2; Surface nette: 0.2 m2; Hauteur: 96 mm; Largeur: 100 mm; Longueur: 392.4 mm
Pset_PlateCommon - LoadBearing: yes; Reference: 211(?)
BaseQuantities - NetArea: 0.220114 m2; GrossArea: 0.220114 m2; CrossSectionArea: 0.002124 m2; NetVolume: 0.000781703 m3; GrossVolume: 0.000833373 m3

# IfcDiscreteAccessory: BECHE (18)
In: Undefined
Material: STEEL/S275-E28
Tekla Commun - Phase: 1; Classe: 3; Matériau: S275-E28; Nom: BECHE
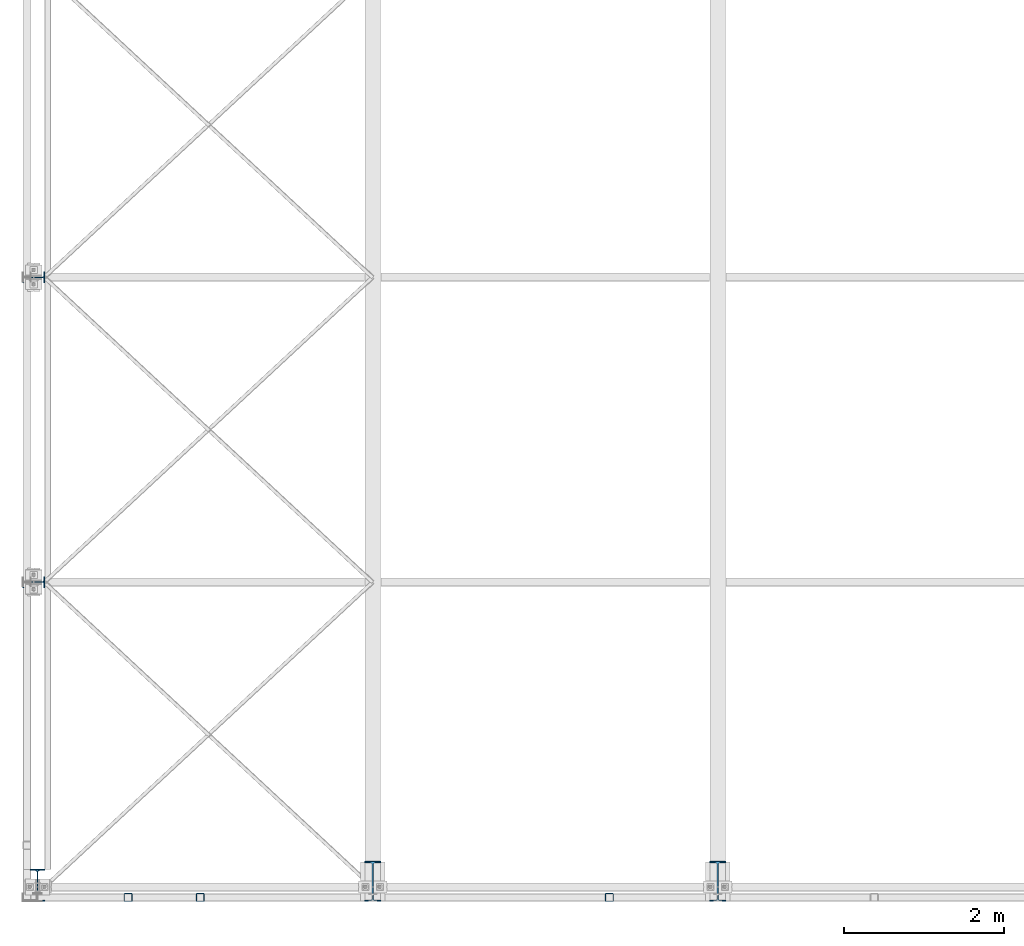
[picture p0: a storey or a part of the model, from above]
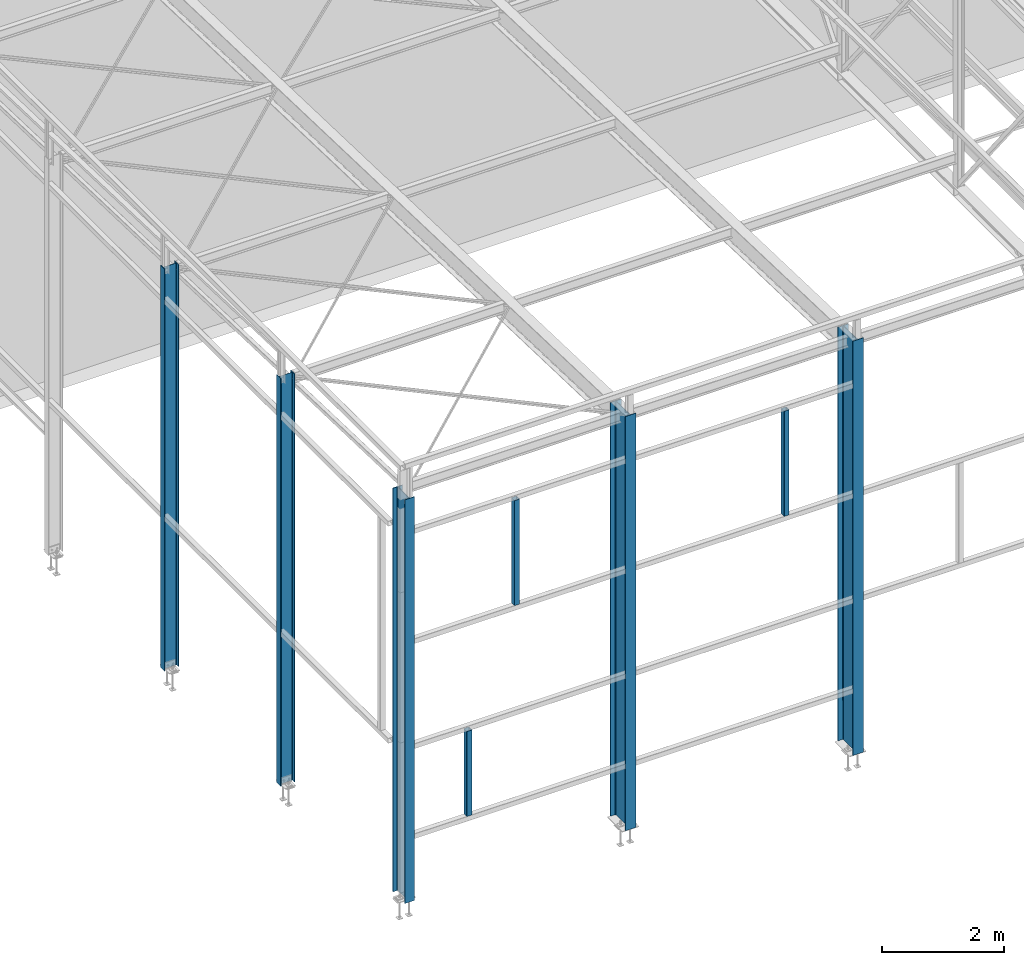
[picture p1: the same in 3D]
Properties of the parts of a building model (IFC2X3), part 2 of 2

# IfcDiscreteAccessory: BECHE (18)
Tekla Quantités - Volume: 0 m3; Surface supérieure totale: 0 m2; Surface nette: 0.1 m2
Pset_PlateCommon - LoadBearing: yes
Name | Description = Profil | Niveau bas | Niveau haut | Repère de pièce = Reference | Repère d'assemblage | Poids (kg) | Surface par tonne (m2) | Hauteur (mm) | Largeur (mm) | Longueur (mm) | NetArea (m2) = GrossArea (m2) | CrossSectionArea (m2) | NetVolume (m3) | GrossVolume (m3)
3 x BECHE | HEA140 | +7.018 | +7.151 | 41(?) | PS4(?) | 2.5 | 32.2 | 133 | 140 | 100 | 0.0794 | 0.003142 | 0.0003018 | 0.0003142
3 x BECHE | HEA140 | +7.443 | +7.576 | 41(?) | PS4(?) | 2.5 | 32.2 | 133 | 140 | 100 | 0.0794 | 0.003142 | 0.0003018 | 0.0003142
BECHE | HEA140 | +7.525 | +7.658 | 42(?) | PS6(?) | 3.1 | 32.2 | 133 | 140 | 125 | 0.09925 | 0.003142 | 0.00037725 | 0.00039275
3 x BECHE | HEA140 | +7.013 | +7.146 | 41 | PS5 | 2.5 | 32.2 | 133 | 140 | 100 | 0.0794 | 0.003142 | 0.0003018 | 0.0003142
3 x BECHE | HEA140 | +7.213 | +7.346 | 41 | PS5 | 2.5 | 32.2 | 133 | 140 | 100 | 0.0794 | 0.003142 | 0.0003018 | 0.0003142
BECHE | HEA100 | +3.267 | +3.363 | 218 | PS1 | 1.8 | 33.6 | 96 | 100 | 100 | 0.0561 | 0.002124 | 0.0002 | 0.0002124
4 x BECHE | HEA120 | -0.380 | -0.260 | 34 | PS3 | 2.5 | 34 | 114 | 120 | 120 | 0.08124 | 0.002534 | 0.0002892 | 0.00030408

# IfcDiscreteAccessory: COIFFE (4)
In: Undefined
Material: STEEL/S235-E24
Tekla Commun - Phase: 1; Classe: 2; Matériau: S235-E24; Nom: COIFFE
Tekla Quantités - Volume: 0 m3; Largeur: 10 mm
Pset_PlateCommon - LoadBearing: yes
Name | Description = Profil | Niveau bas | Niveau haut | Repère de pièce = Reference | Repère d'assemblage | Poids (kg) | Surface supérieure totale (m2) | Surface par tonne (m2) | Surface nette (m2) | Hauteur (mm) | Longueur (mm) | NetArea (m2) = GrossArea (m2) | CrossSectionArea (m2) | NetVolume (m3) = GrossVolume (m3)
2 x COIFFE | PL10*190 | +8.030 | +8.055 | 133(?) | PT0(?) | 7.2 | 0 | 27.3 | 0.2 | 190 | 484.2 | 0.197496 | 0.0019 | 0.000920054
COIFFE | PL10*200 | +8.440 | +8.450 | 0(?) | 0(?) | 7.6 | 0.1 | 27.3 | 0.2 | 200 | 484 | 0.20728 | 0.002 | 0.000968
COIFFE | PL10*135 | +8.030 | +8.055 | 0(?) | 0(?) | 5.1 | 0 | 28 | 0.1 | 135 | 484.2 | 0.143129 | 0.00135 | 0.000653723

# IfcDiscreteAccessory: FEUILLURE (7)
In: Undefined
Material: STEEL/S235-E24
Tekla Commun - Repère de pièce: 0; Repère d'assemblage: 0(?); Phase: 1; Classe: 2; Matériau: S235-E24; Nom: FEUILLURE
Tekla Quantités - Volume: 0 m3; Surface supérieure totale: 0 m2; Largeur: 5 mm
Pset_PlateCommon - LoadBearing: yes; Reference: 0
Name | Description = Profil | Niveau bas | Niveau haut | Poids (kg) | Surface par tonne (m2) | Surface nette (m2) | Hauteur (mm) | Longueur (mm) | NetArea (m2) = GrossArea (m2) | CrossSectionArea (m2) | NetVolume (m3) = GrossVolume (m3)
2 x FEUILLURE | PL100*5 | +8.450 | +10.305 | 7.3 | 53.6 | 0.3 | 100 | 1855 | 0.39055 | 0.0005 | 0.0009275
2 x FEUILLURE | PL100*5 | +8.450 | +11.120 | 10.5 | 53.6 | 0.6 | 100 | 2670 | 0.5617 | 0.0005 | 0.001335
2 x FEUILLURE | PL100*5 | +8.450 | +11.920 | 13.6 | 53.6 | 0.6 | 100 | 3470 | 0.7297 | 0.0005 | 0.001735
FEUILLURE | PL5*270 | +8.275 | +8.545 | 38.5 | 52 | 1.9 | 270 | 3633.5 | 2.00113 | 0.00135 | 0.00490523

# IfcDiscreteAccessory: PLAQUETTE (44)
In: Undefined
Description: PL15*90; Material: STEEL/S235-E24
Tekla Commun - Phase: 1; Classe: 3; Matériau: S235-E24; Profil: PL15*90; Nom: PLAQUETTE
Tekla Quantités - Poids: 0.9 kg; Volume: 0 m3; Surface supérieure totale: 0 m2; Surface par tonne: 22.6 m2; Surface nette: 0 m2; Hauteur: 90 mm; Largeur: 15 mm; Longueur: 90 mm
Pset_PlateCommon - LoadBearing: yes
BaseQuantities - NetArea: 0.0216 m2; GrossArea: 0.0081 m2; CrossSectionArea: 0.000225 m2; NetVolume: 0.0001215 m3; GrossVolume: 0.0001215 m3
Name | Niveau bas | Niveau haut | Repère de pièce = Reference | Repère d'assemblage
14 x PLAQUETTE | -0.235 | -0.220 | 33 | PS2
14 x PLAQUETTE | -0.630 | -0.615 | 32 | PS2
8 x PLAQUETTE | -0.235 | -0.220 | 33 | PS3
8 x PLAQUETTE | -0.630 | -0.615 | 32 | PS3

# IfcDiscreteAccessory: PLAT (16)
In: Undefined
Tekla Commun - Phase: 1; Nom: PLAT
Tekla Quantités - Volume: 0 m3; Surface supérieure totale: 0 m2
Pset_PlateCommon - LoadBearing: yes
Name | Description = Profil | Material | Niveau bas | Niveau haut | Repère de pièce = Reference | Repère d'assemblage | Classe | Matériau | Poids (kg) | Surface par tonne (m2) | Surface nette (m2) | Hauteur (mm) | Largeur (mm) | Longueur (mm) | NetArea (m2) = GrossArea (m2) | CrossSectionArea (m2) | NetVolume (m3) = GrossVolume (m3)
3 x PLAT | PL10*140 | STEEL/S235-E24 | +7.018 | +7.151 | 119(?) | PS4(?) | 3 | S235-E24 | 1.5 | 29.2 | 0 | 140 | 10 | 133 | 0.0427 | 0.0014 | 0.0001862
3 x PLAT | PL10*140 | STEEL/S235-E24 | +7.443 | +7.576 | 119(?) | PS4(?) | 3 | S235-E24 | 1.5 | 29.2 | 0 | 140 | 10 | 133 | 0.0427 | 0.0014 | 0.0001862
PLAT | PL12*140 | STEEL/S235-E24 | +7.525 | +7.658 | 229(?) | PS6(?) | 3 | S235-E24 | 1.8 | 25 | 0 | 140 | 12 | 133 | 0.043792 | 0.00168 | 0.00022344
3 x PLAT | PL10*140 | STEEL/S235-E24 | +7.013 | +7.146 | 119 | PS5 | 3 | S235-E24 | 1.5 | 29.2 | 0 | 140 | 10 | 133 | 0.0427 | 0.0014 | 0.0001862
3 x PLAT | PL10*140 | STEEL/S235-E24 | +7.213 | +7.346 | 119 | PS5 | 3 | S235-E24 | 1.5 | 29.2 | 0 | 140 | 10 | 133 | 0.0427 | 0.0014 | 0.0001862
PLAT | PL10*100 | STEEL/S235-E24 | +3.267 | +3.363 | 118 | PS1 | 3 | S235-E24 | 0.9 | 30.7 | 0 | 100 | 10 | 96 | 0.02312 | 0.001 | 0.000096
PLAT | PL20*80 | STEEL/S235-E24 | +3.255 | +3.375 | 210 | PS1 | 3 | S235-E24 | 1.5 | 18 | 0 | 80 | 20 | 120 | 0.0272 | 0.0016 | 0.000192
PLAT | PL10*140 | STEEL/S275-E28 | +7.858 | +8.058 | 0(?) | 0(?) | 2 | S275-E28 | 2.2 | 28.6 | 0.1 | 140 | 10 | 200 | 0.0628 | 0.0014 | 0.00028

# IfcDiscreteAccessory: PLATINE (23)
In: Undefined
Material: STEEL/S235-E24
Tekla Commun - Phase: 1; Classe: 2; Matériau: S235-E24; Nom: PLATINE
Tekla Quantités - Volume: 0 m3
Pset_PlateCommon - LoadBearing: yes
Name | Description = Profil | Niveau bas | Niveau haut | Repère de pièce = Reference | Repère d'assemblage | Poids (kg) | Surface supérieure totale (m2) | Surface par tonne (m2) | Surface nette (m2) | Hauteur (mm) | Largeur (mm) | Longueur (mm) | NetArea (m2) | GrossArea (m2) | CrossSectionArea (m2) | NetVolume (m3) | GrossVolume (m3)
4 x PLATINE | PL15*490 | -0.250 | -0.235 | 28(?) | PT0(?) | 17.9 | 0.2 | 18.3 | 0.3 | 490 | 15 | 310 | 0.3278 | 0.3278 | 0.00735 | 0.0022785 | 0.0022785
5 x PLATINE | PL10*150 | -0.100 | -0.090 | 131 | M0(?) | 1.2 | 0 | 29.5 | 0 | 150 | 10 | 110 | 0.0382 | 0.0382 | 0.0015 | 0.000165 | 0.000165 | Tekla Commun - Finition: GALVA
2 x PLATINE | PL5*581 | +8.450 | +8.540 | 137 | PT0(?) | 2.1 | 0 | 54.2 | 0.1 | 581 | 5 | 90 | 0.11129 | 0.11129 | 0.002905 | 0.00026145 | 0.00026145
2 x PLATINE | PL10*290 | +8.540 | +8.550 | 108 | PT0(?) | 13.2 | 0.2 | 26.8 | 0.3 | 290 | 10 | 581 | 0.3544 | 0.3544 | 0.0029 | 0.0016849 | 0.0016849
8 x PLATINE | PL15*103.5 | -0.235 | +0.007 | 27 | PT0(?) | 3.3 | 0 | 20.4 | 0.1 | 103.5 | 15 | 269 | 0.0662933 | 0.066869 | 0.0015525 | 0.000414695 | 0.000417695
2 x PLATINE | PL15*300 | -0.250 | -0.235 | 29 | PT0(?) | 11 | 0.1 | 18.7 | 0.2 | 300 | 15 | 310 | 0.2043 | 0.2043 | 0.0045 | 0.001395 | 0.001395

# IfcDiscreteAccessory: PRESCELLEMENT (8)
In: Undefined
Material: STEEL/S235-E24
Tekla Commun - Phase: 1; Classe: 3; Matériau: S235-E24; Nom: PRESCELLEMENT
Tekla Quantités - Volume: 0 m3; Surface supérieure totale: 0 m2
Pset_PlateCommon - LoadBearing: yes
Name | Description = Profil | Niveau bas | Niveau haut | Repère de pièce = Repère d'assemblage = Reference | Poids (kg) | Surface par tonne (m2) | Surface nette (m2) | Hauteur (mm) | Largeur (mm) | Longueur (mm) | NetArea (m2) = GrossArea (m2) | CrossSectionArea (m2) | NetVolume (m3) = GrossVolume (m3)
3 x PRESCELLEMENT | PL12*300 | +6.970 | +7.625 | PS4(?) | 18.5 | 22.5 | 0.3 | 300 | 12 | 655 | 0.41592 | 0.0036 | 0.002358
PRESCELLEMENT | PL12*250 | +7.477 | +7.707 | PS6(?) | 5.3 | 23.4 | 0.1 | 250 | 12 | 230 | 0.12652 | 0.003 | 0.00069
3 x PRESCELLEMENT | PL12*300 | +6.965 | +7.395 | PS5 | 12.1 | 22.7 | 0.3 | 300 | 12 | 430 | 0.27552 | 0.0036 | 0.001548
PRESCELLEMENT | PL10*250 | +3.200 | +3.430 | PS1 | 4.4 | 27.6 | 0.1 | 250 | 10 | 230 | 0.1246 | 0.0025 | 0.000575

# IfcDiscreteAccessory: PRESCELLEMENT PS24 (11)
In: Undefined
Description: PL10*150; Material: STEEL/S235-E24
Tekla Commun - Niveau bas: -0.260; Niveau haut: -0.250; Phase: 1; Classe: 3; Matériau: S235-E24; Profil: PL10*150; Nom: PRESCELLEMENT PS24
Tekla Quantités - Poids: 4.2 kg; Volume: 0 m3; Surface supérieure totale: 0.1 m2; Surface par tonne: 28 m2; Surface nette: 0.1 m2; Hauteur: 150 mm; Largeur: 10 mm; Longueur: 350 mm
Pset_PlateCommon - LoadBearing: yes
BaseQuantities - NetArea: 0.115094 m2; GrossArea: 0.115 m2; CrossSectionArea: 0.0015 m2; NetVolume: 0.000523 m3; GrossVolume: 0.000525 m3
Name | Repère de pièce = Repère d'assemblage = Reference
7 x PRESCELLEMENT PS24 | PS2
4 x PRESCELLEMENT PS24 | PS3

# IfcDiscreteAccessory: RAIDISSEUR (38)
In: Undefined
Material: STEEL/S235-E24
Tekla Commun - Phase: 1; Classe: 2; Matériau: S235-E24; Nom: RAIDISSEUR
Tekla Quantités - Volume: 0 m3; Surface supérieure totale: 0 m2
Pset_PlateCommon - LoadBearing: yes
Name | Description = Profil | Niveau bas | Niveau haut | Repère de pièce = Reference | Repère d'assemblage | Poids (kg) | Surface par tonne (m2) | Surface nette (m2) | Hauteur (mm) | Largeur (mm) | Longueur (mm) | NetArea (m2) | GrossArea (m2) | CrossSectionArea (m2) | NetVolume (m3) = GrossVolume (m3)
4 x RAIDISSEUR | PL10*110 | +7.017 | +7.594 | 111(?) | S0(?) | 3 | 29.8 | 0.1 | 110 | 10 | 576.5 | 0.0882117 | 0.0633877 | 0.0001 | 0.000377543
8 x RAIDISSEUR | TOLE10*60 | +7.127 | +7.240 | 225(?) | L0(?) | 0.5 | 32.1 | 0 | 60 | 10 | 114 | 0.0157144 | 0.00684 | 0.0001 | 0.0000624
2 x RAIDISSEUR | PL10*155 | +7.117 | +7.272 | 115 | S0(?) | 1.2 | 29.9 | 0 | 155 | 10 | 170 | 0.0370421 | 0.0263499 | 0.0001 | 0.000157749
8 x RAIDISSEUR | TOLE10*80 | +7.090 | +7.239 | 224 | L0(?) | 0.9 | 30.3 | 0 | 80 | 10 | 150 | 0.0271544 | 0.012 | 0.0001 | 0.000114
2 x RAIDISSEUR | PL10*170 | +7.079 | +7.274 | 114 | S0(?) | 1.5 | 29.5 | 0 | 170 | 10 | 195 | 0.045329 | 0.0331499 | 0.0001 | 0.000195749
8 x RAIDISSEUR | TOLE10*90 | +7.071 | +7.239 | 223(?) | L0(?) | 1.1 | 29.8 | 0 | 90 | 10 | 168 | 0.0339544 | 0.01512 | 0.0001 | 0.0001452
2 x RAIDISSEUR | PL10*170 | +7.060 | +7.275 | 113 | S0(?) | 1.8 | 29.5 | 0 | 170 | 10 | 215 | 0.0494843 | 0.0365499 | 0.0001 | 0.000214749
2 x RAIDISSEUR | PL10*110 | +7.014 | +7.490 | 112 | S0(?) | 2.5 | 29.8 | 0.1 | 110 | 10 | 476.4 | 0.0732427 | 0.0523743 | 0.0001 | 0.000312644
2 x RAIDISSEUR | PL5*90 | +8.450 | +8.540 | 138 | PT0(?) | 0.6 | 55.2 | 0 | 90 | 5 | 168 | 0.0319028 | 0.01512 | 0.000025 | 0.0000736

# IfcDiscreteAccessory: SABOT (12)
In: Undefined
Description: PL10*260; Material: STEEL/S235-E24
Tekla Commun - Repère d'assemblage: S0(?); Phase: 1; Classe: 2; Matériau: S235-E24; Profil: PL10*260; Nom: SABOT
Tekla Quantités - Volume: 0 m3; Surface supérieure totale: 0 m2; Hauteur: 260 mm; Largeur: 10 mm
Pset_PlateCommon - LoadBearing: yes
BaseQuantities - CrossSectionArea: 0.0026 m2
Name | Niveau bas | Niveau haut | Repère de pièce = Reference | Poids (kg) | Surface par tonne (m2) | Surface nette (m2) | Longueur (mm) | NetArea (m2) = GrossArea (m2) | NetVolume (m3) = GrossVolume (m3)
2 x SABOT | +7.006 | +7.020 | 125(?) | 2.2 | 28.8 | 0.1 | 110 | 0.0646066 | 0.000286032
2 x SABOT | +7.000 | +7.595 | S0(?) | 12.1 | 26.9 | 0.3 | 595 | 0.3265 | 0.001547
SABOT | +7.107 | +7.117 | 117 | 3.5 | 28 | 0.1 | 170 | 0.097 | 0.000442
SABOT | +7.092 | +7.272 | S0 | 3.7 | 28 | 0.1 | 180 | 0.1024 | 0.000468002
SABOT | +7.069 | +7.079 | 116 | 3.5 | 28 | 0.1 | 170 | 0.097 | 0.000442
SABOT | +7.054 | +7.274 | S0 | 4.4 | 27.6 | 0.1 | 220 | 0.124 | 0.000572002
SABOT | +7.050 | +7.060 | 116 | 3.5 | 28 | 0.1 | 170 | 0.097 | 0.000442
SABOT | +7.035 | +7.275 | S0 | 4.9 | 27.5 | 0.1 | 240 | 0.1348 | 0.000624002
SABOT | +7.003 | +7.016 | 126 | 2.2 | 28.8 | 0.1 | 110 | 0.0646066 | 0.000286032
SABOT | +6.995 | +7.490 | S0 | 10.1 | 26.9 | 0.3 | 495 | 0.2725 | 0.001287

# IfcDiscreteAccessory: TIGE D'ANCRAGE (44)
In: Undefined
Material: STEEL/S235-E24
Tekla Commun - Phase: 1; Classe: 3; Matériau: S235-E24; Nom: TIGE D'ANCRAGE
Tekla Quantités - Volume: 0 m3; Surface supérieure totale: 0 m2; Surface nette: 0 m2
Pset_PlateCommon - LoadBearing: yes
Name | Description = Profil | Niveau bas | Niveau haut | Repère de pièce = Reference | Repère d'assemblage | Poids (kg) | Surface par tonne (m2) | Hauteur (mm) = Largeur (mm) | Longueur (mm) | NetArea (m2) = GrossArea (m2) | CrossSectionArea (m2) | NetVolume (m3) = GrossVolume (m3)
14 x TIGE D'ANCRAGE | D24 | -0.300 | -0.150 | 201 | PS2 | 0.5 | 23.7 | 24 | 150 | 0.012045 | 0.000432 | 0.0000648
14 x TIGE D'ANCRAGE | D22 | -0.650 | -0.300 | 200 | PS2 | 0.9 | 24.7 | 22 | 350 | 0.0246409 | 0.000363 | 0.00012705
8 x TIGE D'ANCRAGE | D24 | -0.300 | -0.150 | 201 | PS3 | 0.5 | 23.7 | 24 | 150 | 0.012045 | 0.000432 | 0.0000648
8 x TIGE D'ANCRAGE | D22 | -0.650 | -0.300 | 200 | PS3 | 0.9 | 24.7 | 22 | 350 | 0.0246409 | 0.000363 | 0.00012705

# IfcDiscreteAccessory: TRAVERSE SHED (13)
In: Undefined
Material: STEEL/S275-E28
Tekla Commun - Niveau haut: +8.550; Repère d'assemblage: TS0(?); Phase: 1; Classe: 2; Matériau: S275-E28; Nom: TRAVERSE SHED
Tekla Quantités - Volume: 0 m3; Surface supérieure totale: 0 m2
Pset_PlateCommon - LoadBearing: yes
Name | Description = Profil | Niveau bas | Repère de pièce = Reference | Poids (kg) | Surface par tonne (m2) | Surface nette (m2) | Hauteur (mm) | Largeur (mm) | Longueur (mm) | NetArea (m2) = GrossArea (m2) | CrossSectionArea (m2) | NetVolume (m3) | GrossVolume (m3)
TRAVERSE SHED | IPE200 | +8.050 | 71(?) | 11.2 | 34.3 | 0.3 | 200 | 100 | 500 | 0.383999 | 0.00285 | 0.00119273 | 0.00142499
TRAVERSE SHED | IPE200 | +7.572 | 70(?) | 21.9 | 34.3 | 0.6 | 200 | 100 | 977.7 | 0.750858 | 0.00285 | 0.00249432 | 0.00278639
TRAVERSE SHED | IPE200 | +7.692 | 69(?) | 19.3 | 34.3 | 0.6 | 200 | 100 | 858.3 | 0.659143 | 0.00285 | 0.00216892 | 0.00244604
TRAVERSE SHED | IPE200 | +7.811 | 68(?) | 16.5 | 34.3 | 0.5 | 200 | 100 | 738.8 | 0.567428 | 0.00285 | 0.00184352 | 0.00210569
TRAVERSE SHED | IPE200 | +7.931 | 67(?) | 13.9 | 34.3 | 0.3 | 200 | 100 | 619.5 | 0.475761 | 0.00285 | 0.0015183 | 0.00176552
TRAVERSE SHED | IPE200 | +7.572 | 64(?) | 21.9 | 34.3 | 0.6 | 200 | 100 | 977.7 | 0.750858 | 0.00285 | 0.00249829 | 0.00278639
TRAVERSE SHED | IPE200 | +7.692 | 63(?) | 19.3 | 34.3 | 0.6 | 200 | 100 | 858.3 | 0.659143 | 0.00285 | 0.00217289 | 0.00244604
TRAVERSE SHED | IPE200 | +7.811 | 62(?) | 16.5 | 34.3 | 0.5 | 200 | 100 | 738.8 | 0.567429 | 0.00285 | 0.0018475 | 0.00210569
TRAVERSE SHED | IPE200 | +7.931 | 61(?) | 13.9 | 34.3 | 0.3 | 200 | 100 | 619.5 | 0.475714 | 0.00285 | 0.0015221 | 0.00176535
TRAVERSE SHED | IPE240 | +7.931 | 76(?) | 19 | 29.9 | 0.5 | 240 | 120 | 619.5 | 0.571105 | 0.003909 | 0.00203314 | 0.00242131
TRAVERSE SHED | IPE240 | +7.572 | 75(?) | 30 | 29.9 | 0.9 | 240 | 120 | 977.7 | 0.90142 | 0.003909 | 0.00336532 | 0.00382175
TRAVERSE SHED | IPE240 | +7.692 | 74(?) | 26.3 | 29.9 | 0.9 | 240 | 120 | 858.3 | 0.791315 | 0.003909 | 0.00292126 | 0.00335494
TRAVERSE SHED | IPE240 | +7.811 | 73(?) | 22.7 | 29.9 | 0.6 | 240 | 120 | 738.8 | 0.68121 | 0.003909 | 0.0024772 | 0.00288812

# IfcElementAssembly (475)
In: Undefined
Name | PredefinedType | Poids Assemblage/Elément béton (kg) | Niveau Bas Assemblage/Elément béton | Niveau Haut Assemblage/Elément béton | Position maillage Assemblage/Elément béton | Repère Assemblage/Elément béton | Width (mm)
2 x Steel Assembly | RIGID_FRAME | 23.2 | +8.023 | +8.197 | C9/CA-CB | L0(?) | 50
2 x Steel Assembly | RIGID_FRAME | 22.3 | +8.147 | +8.316 | C9/CA-CB | L0(?) | 50
2 x Steel Assembly | RIGID_FRAME | 22.3 | +8.266 | +8.436 | C9/CA-CB | L0(?) | 50
Steel Assembly | RIGID_FRAME | 23.2 | +8.023 | +8.197 | C8/CA-CB | L0(?) | 50
Steel Assembly | RIGID_FRAME | 22.3 | +8.147 | +8.316 | C8/CA-CB | L0(?) | 50
Steel Assembly | RIGID_FRAME | 22.3 | +8.266 | +8.436 | C8/CA-CB | L0(?) | 50
Steel Assembly | RIGID_FRAME | 23.2 | +8.023 | +8.197 | C6/CA-CB | L0(?) | 50
Steel Assembly | RIGID_FRAME | 22.3 | +8.147 | +8.316 | C6/CA-CB | L0(?) | 50
Steel Assembly | RIGID_FRAME | 22.3 | +8.266 | +8.436 | C6/CA-CB | L0(?) | 50
Steel Assembly | RIGID_FRAME | 23.2 | +8.023 | +8.197 | C8'/CA-CB | L0(?) | 50
Steel Assembly | RIGID_FRAME | 22.3 | +8.147 | +8.316 | C8'/CA-CB | L0(?) | 50
Steel Assembly | RIGID_FRAME | 22.3 | +8.266 | +8.436 | C8'/CA-CB | L0(?) | 50
Steel Assembly | RIGID_FRAME | 23.2 | +8.023 | +8.197 | C7/CA-CB | L0(?) | 50
Steel Assembly | RIGID_FRAME | 22.3 | +8.147 | +8.316 | C7/CA-CB | L0(?) | 50
Steel Assembly | RIGID_FRAME | 22.3 | +8.266 | +8.436 | C7/CA-CB | L0(?) | 50
2 x Steel Assembly | RIGID_FRAME | 7.2 | +7.220 | +8.445 | 1/E | B0(?) | 50
2 x Steel Assembly | RIGID_FRAME | 4.4 | +7.690 | +8.445 | C1/CA | B0(?) | 50
Steel Assembly | RIGID_FRAME | 20.3 | +7.000 | +7.595 | C7/CB | S0(?) | 120.272
Steel Assembly | RIGID_FRAME | 26.4 | +6.970 | +7.625 | C7/CB | PS4(?) | 122
Steel Assembly | RIGID_FRAME | 785.7 | -0.250 | +8.445 | C3/CA | PT0(?) | 310
Steel Assembly | RIGID_FRAME | 2.8 | +7.016 | +7.119 | C3/CB | A0(?) | 100.265
2 x Steel Assembly | RIGID_FRAME | 4.2 | +7.203 | +7.483 | C3/CB | A0(?) | 100
Steel Assembly | RIGID_FRAME | 1168.1 | +7.117 | +8.040 | C3/CA-CB | T0(?) | 190
Steel Assembly | RIGID_FRAME | 771.9 | -0.250 | +8.046 | C9/CA | PT0(?) | 310
Steel Assembly | RIGID_FRAME | 807.8 | -0.250 | +8.440 | C8/CA | PT0(?) | 310
DALLE | REINFORCEMENT_UNIT | 3377.1 | +8.550 | +11.187 | 6-8/E | Da0(?) | 200 | Tekla Assemblages - Poids ferraillage Elément béton: 0 kg
DALLE | REINFORCEMENT_UNIT | 5561.6 | +8.550 | +12.015 | 4-7/E | Da0(?) | 200 | Tekla Assemblages - Poids ferraillage Elément béton: 0 kg
DALLE | REINFORCEMENT_UNIT | 8363 | +8.550 | +12.819 | 2-5/E | Da0(?) | 200 | Tekla Assemblages - Poids ferraillage Elément béton: 0 kg
2 x Steel Assembly | RIGID_FRAME | 3.9 | +7.775 | +8.445 | C1/CA-CB | B0(?) | 50
2 x Steel Assembly | RIGID_FRAME | 4.6 | +7.655 | +8.445 | C1/CA-CB | B0(?) | 50
2 x Steel Assembly | RIGID_FRAME | 5.3 | +7.535 | +8.445 | C1/CA-CB | B0(?) | 50
Steel Assembly | RIGID_FRAME | 11.8 | +8.577 | +9.201 | C8-C8'/CA | F0(?) | 165
Steel Assembly | RIGID_FRAME | 26.8 | +8.574 | +9.956 | C6-C7/CA | F0(?) | 165
Steel Assembly | RIGID_FRAME | 14.3 | +8.565 | +9.355 | C4-C5/CA | F0(?) | 160
Steel Assembly | RIGID_FRAME | 27.7 | +9.284 | +10.745 | C4-C5/CA | F0(?) | 160
Steel Assembly | RIGID_FRAME | 28.3 | +9.129 | +10.524 | C8-C8'/CA | F0(?) | 165
Steel Assembly | RIGID_FRAME | 28.3 | +9.885 | +11.336 | C6-C7/CA | F0(?) | 165
Steel Assembly | RIGID_FRAME | 27.7 | +10.674 | +12.136 | C4-C5/CA | F0(?) | 160
Steel Assembly | RIGID_FRAME | 32.7 | +5.000 | +8.550 | C6/CA | M0(?) | 80
2 x Steel Assembly | RIGID_FRAME | 35 | +5.104 | +8.435 | C4-C5/CA | D0(?) | 70
2 x Steel Assembly | RIGID_FRAME | 35 | +5.105 | +8.435 | C4-C5/CA | D0(?) | 70
4 x Steel Assembly | RIGID_FRAME | 28.3 | +5.112 | +8.428 | C5-C6/CA | D0(?) | 70
4 x Steel Assembly | RIGID_FRAME | 31.4 | +5.108 | +8.432 | C6-C7/CA | D0(?) | 70
2 x Steel Assembly | RIGID_FRAME | 5.3 | +7.940 | +8.270 | C6-C7/CA | M0(?) | 60
2 x Steel Assembly | RIGID_FRAME | 48.2 | +5.260 | +8.270 | C6-C7/CA | M0(?) | 60
2 x Steel Assembly | RIGID_FRAME | 48.2 | +5.260 | +8.270 | C5-C6/CA | M0(?) | 60
2 x Steel Assembly | RIGID_FRAME | 5.3 | +7.940 | +8.270 | C4-C5/CA | M0(?) | 60
2 x Steel Assembly | RIGID_FRAME | 48.2 | +5.260 | +8.270 | C6/CA | M0(?) | 60
2 x Steel Assembly | RIGID_FRAME | 48.2 | +5.260 | +8.270 | C5/CA | M0(?) | 60
2 x Steel Assembly | RIGID_FRAME | 48.2 | +5.260 | +8.270 | C4-C5/CA | M0(?) | 60
2 x Steel Assembly | RIGID_FRAME | 653.9 | +8.270 | +8.550 | C4-C7/CA | TH0(?) | 95
2 x Steel Assembly | RIGID_FRAME | 591.5 | +5.000 | +5.260 | C4-C7/CA | TB0(?) | 90
Steel Assembly | RIGID_FRAME | 17 | +8.560 | +10.400 | C8/CA | F0(?) | 160
Steel Assembly | RIGID_FRAME | 24.4 | +8.560 | +11.210 | C6/CA | F0(?) | 160
Steel Assembly | RIGID_FRAME | 16.1 | +10.260 | +12.010 | C4/CA | F0(?) | 160
Steel Assembly | RIGID_FRAME | 15.7 | +8.560 | +10.260 | C4/CA | F0(?) | 160
Steel Assembly | RIGID_FRAME | 7.3 | +8.450 | +10.305 | C8/CA | 0(?) | 5
Steel Assembly | RIGID_FRAME | 7.3 | +8.450 | +10.305 | C8/CB | 0(?) | 5
Steel Assembly | RIGID_FRAME | 10.5 | +8.450 | +11.120 | C6/CA | 0(?) | 5
Steel Assembly | RIGID_FRAME | 10.5 | +8.450 | +11.120 | C6/CB | 0(?) | 5
Steel Assembly | RIGID_FRAME | 13.6 | +8.450 | +11.920 | C4/CA | 0(?) | 5
Steel Assembly | RIGID_FRAME | 13.6 | +8.450 | +11.920 | C4/CB | 0(?) | 5
Steel Assembly | RIGID_FRAME | 2.2 | +8.450 | +8.550 | 1/E | A0(?) | 130
Steel Assembly | RIGID_FRAME | 181.8 | +8.450 | +8.550 | C1/CA-CB | L0(?) | 100
Steel Assembly | RIGID_FRAME | 181.8 | +8.450 | +8.550 | C9/CA-CB | L0(?) | 100
Steel Assembly | RIGID_FRAME | 2.2 | +8.450 | +8.550 | C9/CB | A0(?) | 130
Steel Assembly | RIGID_FRAME | 14.6 | +7.572 | +8.445 | C9/CB | 0(?) | 100
Steel Assembly | RIGID_FRAME | 8.6 | +7.931 | +8.445 | C9/CA-CB | 0(?) | 100
Steel Assembly | RIGID_FRAME | 10.6 | +7.811 | +8.445 | C9/CA-CB | 0(?) | 100
Steel Assembly | RIGID_FRAME | 12.6 | +7.692 | +8.445 | C9/CA-CB | 0(?) | 100
Steel Assembly | RIGID_FRAME | 10.3 | +7.477 | +7.707 | 3/E | PS6(?) | 149
2 x Steel Assembly | RIGID_FRAME | 3.6 | +7.970 | +8.210 | 7/E | A0(?) | 100
Steel Assembly | RIGID_FRAME | 3.6 | +7.970 | +8.210 | 4-5/E | A0(?) | 100
Steel Assembly | RIGID_FRAME | 3.6 | +7.970 | +8.210 | 5/E | A0(?) | 100
Steel Assembly | RIGID_FRAME | 3.6 | +7.970 | +8.210 | 2-3/E | A0(?) | 100
Steel Assembly | RIGID_FRAME | 3.6 | +7.970 | +8.210 | 3/E | A0(?) | 100
Steel Assembly | RIGID_FRAME | 374.9 | +7.117 | +7.250 | C8/CA-CB | L0(?) | 140
Steel Assembly | RIGID_FRAME | 9.6 | +7.092 | +7.272 | C8/CB | S0(?) | 180
Steel Assembly | RIGID_FRAME | 20 | +6.965 | +7.395 | C8/CB | PS5 | 122
Steel Assembly | RIGID_FRAME | 552.4 | +7.079 | +7.250 | C6/CA-CB | L0(?) | 180
Steel Assembly | RIGID_FRAME | 11 | +7.054 | +7.274 | C6/CB | S0(?) | 180
Steel Assembly | RIGID_FRAME | 20 | +6.965 | +7.395 | C6/CB | PS5 | 122
Steel Assembly | RIGID_FRAME | 657.8 | +7.060 | +7.250 | C4/CA-CB | L0(?) | 200
Steel Assembly | RIGID_FRAME | 11.8 | +7.035 | +7.275 | C4/CB | S0(?) | 180
Steel Assembly | RIGID_FRAME | 20 | +6.965 | +7.395 | C4/CB | PS5 | 122
Steel Assembly | RIGID_FRAME | 17.3 | +6.995 | +7.490 | C8'/CB | S0(?) | 120.294
Steel Assembly | RIGID_FRAME | 26.4 | +6.970 | +7.625 | C8'/CB | PS4(?) | 122
Steel Assembly | RIGID_FRAME | 20.3 | +7.000 | +7.595 | 4/E | S0(?) | 120.272
Steel Assembly | RIGID_FRAME | 26.4 | +6.970 | +7.625 | 4/E | PS4(?) | 122
Steel Assembly | RIGID_FRAME | 2 | +7.092 | +7.196 | C9/CB | A0(?) | 100.306
2 x Steel Assembly | RIGID_FRAME | 2.7 | +7.240 | +7.420 | C9/CB | A0(?) | 100
Steel Assembly | RIGID_FRAME | 2.8 | +7.016 | +7.119 | C2/CB | A0(?) | 100.265
2 x Steel Assembly | RIGID_FRAME | 4.2 | +7.203 | +7.483 | C2/CB | A0(?) | 100
2 x Steel Assembly | RIGID_FRAME | 1.2 | +3.255 | +3.375 | 1/E | A0(?) | 80
Steel Assembly | RIGID_FRAME | 8.4 | +3.200 | +3.430 | 1/E | PS1 | 200
3 x Steel Assembly | RIGID_FRAME | 10.3 | +8.240 | +9.775 | C8-C8'/CA-CB | S0(?) | 50
3 x Steel Assembly | RIGID_FRAME | 15.3 | +8.240 | +10.512 | C6-C7/CA-CB | S0(?) | 50
3 x Steel Assembly | RIGID_FRAME | 20.4 | +8.240 | +11.261 | C4-C5/CA-CB | S0(?) | 50
7 x Steel Assembly | RIGID_FRAME | 6.2 | +7.985 | +8.045 | C6-C7/CA-CB | S0(?) | 60
Steel Assembly | RIGID_FRAME | 6.2 | +7.985 | +8.045 | 4-5/E | S0(?) | 60
Steel Assembly | RIGID_FRAME | 5.5 | +7.985 | +8.045 | C6-C7/CA | S0(?) | 60
Steel Assembly | RIGID_FRAME | 247.3 | +7.940 | +8.240 | C6-C7/CA-CB | L0(?) | 82.5
7 x Steel Assembly | RIGID_FRAME | 6.2 | +7.985 | +8.045 | C8-C8'/CA-CB | S0(?) | 60
Steel Assembly | RIGID_FRAME | 6.2 | +7.985 | +8.045 | 6-7/E | S0(?) | 60
Steel Assembly | RIGID_FRAME | 247.3 | +7.940 | +8.240 | C8-C8'/CA-CB | L0(?) | 82.5
7 x Steel Assembly | RIGID_FRAME | 6.2 | +7.985 | +8.045 | C4-C5/CA-CB | S0(?) | 60
Steel Assembly | RIGID_FRAME | 6.2 | +7.985 | +8.045 | 2-3/E | S0(?) | 60
Steel Assembly | RIGID_FRAME | 4.2 | +7.985 | +8.045 | C4-C5/CA | S0(?) | 60
Steel Assembly | RIGID_FRAME | 50.7 | +7.542 | +7.642 | C4-C5/CA-CB | B0(?) | 100
Steel Assembly | RIGID_FRAME | 25.7 | +5.103 | +7.192 | C6/CA-CB | B0(?) | 80
Steel Assembly | RIGID_FRAME | 29.2 | +5.106 | +7.683 | C7/CA-CB | B0(?) | 80
Steel Assembly | RIGID_FRAME | 29.6 | +5.106 | +7.739 | C5/CA-CB | B0(?) | 80
Steel Assembly | RIGID_FRAME | 25.6 | +5.103 | +7.182 | C4/CA-CB | B0(?) | 80
Steel Assembly | RIGID_FRAME | 11 | -0.650 | -0.150 | 1/E | PS2 | 500
3 x Steel Assembly | RIGID_FRAME | 11 | -0.650 | -0.150 | C1/CA-CB | PS2 | 500
DALLE | REINFORCEMENT_UNIT | 283214 | -0.250 | +0.000 | 1-9/E-A | Da0(?) | 250 | Tekla Assemblages - Poids ferraillage Elément béton: 0 kg
DALLE | REINFORCEMENT_UNIT | 149095 | +3.200 | +3.430 | 4-9/E-A | Da0(?) | 230 | Tekla Assemblages - Poids ferraillage Elément béton: 0 kg
POUTRE | REINFORCEMENT_UNIT | 37962 | +0.000 | +8.550 | 4/E-A | Po0(?) | 200 | Tekla Assemblages - Poids ferraillage Elément béton: 0 kg
POUTRE | REINFORCEMENT_UNIT | 38372.4 | +0.000 | +8.550 | 3/E-A | Po0(?) | 200 | Tekla Assemblages - Poids ferraillage Elément béton: 0 kg
POUTRE | REINFORCEMENT_UNIT | 29789.8 | +0.000 | +4.550 | 1-3/A | Po0(?) | 200 | Tekla Assemblages - Poids ferraillage Elément béton: 0 kg
DALLE | REINFORCEMENT_UNIT | 149095 | +7.830 | +8.060 | 4-9/E-A | Da0(?) | 230 | Tekla Assemblages - Poids ferraillage Elément béton: 0 kg
DALLE | REINFORCEMENT_UNIT | 71043.3 | +3.200 | +3.430 | 1-3/E-A | Da0(?) | 230 | Tekla Assemblages - Poids ferraillage Elément béton: 0 kg
Steel Assembly | RIGID_FRAME | 21.4 | -0.100 | +2.100 | C1/CA-CB | M0(?) | 110
Steel Assembly | RIGID_FRAME | 28.6 | -0.100 | +2.886 | 6-7/A> | M0(?) | 110
Steel Assembly | RIGID_FRAME | 29.1 | -0.100 | +2.945 | 6-7/A> | M0(?) | 110
Steel Assembly | RIGID_FRAME | 28.6 | -0.100 | +2.886 | 6/A> | M0(?) | 110
Steel Assembly | RIGID_FRAME | 29.1 | -0.100 | +2.945 | 6/A> | M0(?) | 110
2 x Steel Assembly | RIGID_FRAME | 4.2 | -0.250 | -0.100 | 6''/A' | A0(?) | 150
2 x Steel Assembly | RIGID_FRAME | 4.2 | -0.250 | -0.100 | 6'/A' | A0(?) | 150
2 x Steel Assembly | RIGID_FRAME | 6.5 | +2.926 | +2.982 | 6'-6''/A' | F0(?) | 50.0885
2 x Steel Assembly | RIGID_FRAME | 10.5 | -0.244 | +2.814 | 6'-6''/A' | S0(?) | 40
Steel Assembly | RIGID_FRAME | 17.7 | +1.600 | +1.650 | 6'-6''/A' | L0(?) | 50
Steel Assembly | RIGID_FRAME | 17.7 | +0.100 | +0.150 | 6'-6''/A' | L0(?) | 50
Steel Assembly | RIGID_FRAME | 10.3 | +2.040 | +2.090 | 6/A> | L0(?) | 50
Steel Assembly | RIGID_FRAME | 6.7 | +1.600 | +1.650 | 6/A> | L0(?) | 50
Steel Assembly | RIGID_FRAME | 10.3 | +1.600 | +1.650 | 6/A> | L0(?) | 50
Steel Assembly | RIGID_FRAME | 6.7 | +0.100 | +0.150 | 6/A> | L0(?) | 50
Steel Assembly | RIGID_FRAME | 10.3 | +0.100 | +0.150 | 6/A> | L0(?) | 50
Steel Assembly | RIGID_FRAME | 10.3 | +2.040 | +2.090 | 6-7/A> | L0(?) | 50
Steel Assembly | RIGID_FRAME | 6.7 | +1.600 | +1.650 | 6-7/A> | L0(?) | 50
Steel Assembly | RIGID_FRAME | 10.3 | +1.600 | +1.650 | 6-7/A> | L0(?) | 50
Steel Assembly | RIGID_FRAME | 6.7 | +0.100 | +0.150 | 6-7/A> | L0(?) | 50
Steel Assembly | RIGID_FRAME | 10.3 | +0.100 | +0.150 | 6-7/A> | L0(?) | 50
Steel Assembly | RIGID_FRAME | 10.3 | +2.938 | +3.198 | 6/A> | S0(?) | 40
Steel Assembly | RIGID_FRAME | 10.3 | +2.938 | +3.198 | 6-7/A> | S0(?) | 40
Steel Assembly | RIGID_FRAME | 14.3 | +3.034 | +4.925 | 7-8/A> | B0(?) | 60.3
Steel Assembly | RIGID_FRAME | 14.3 | +3.034 | +4.925 | 5/A> | B0(?) | 60.3
Steel Assembly | RIGID_FRAME | 67.7 | +2.816 | +3.200 | 5/A> | T0(?) | 82
Steel Assembly | RIGID_FRAME | 67.7 | +2.816 | +3.200 | 7-8/A> | T0(?) | 82
Steel Assembly | RIGID_FRAME | 12.2 | +2.941 | +3.190 | 6-7/A> | S0(?) | 40
Steel Assembly | RIGID_FRAME | 12.2 | +2.939 | +3.190 | 6-7/A> | S0(?) | 40
Steel Assembly | RIGID_FRAME | 67.7 | +2.816 | +3.200 | 6-7/A> | T0(?) | 82
Steel Assembly | RIGID_FRAME | 114 | +3.188 | +3.311 | 5-8/A | PN0(?) | 64
Steel Assembly | RIGID_FRAME | 114 | +3.083 | +3.206 | 5-8/A> | PN0(?) | 64
Steel Assembly | RIGID_FRAME | 114 | +2.978 | +3.102 | 4'-7'/A' | PN0(?) | 64
Steel Assembly | RIGID_FRAME | 67.7 | +2.816 | +3.200 | 6/A> | T0(?) | 82
Steel Assembly | RIGID_FRAME | 48.2 | -0.230 | +2.824 | 6''/A' | PT0(?) | 82
Steel Assembly | RIGID_FRAME | 48.2 | -0.230 | +2.824 | 6'/A' | PT0(?) | 82
Steel Assembly | RIGID_FRAME | 13.6 | +8.000 | +8.550 | C8-C8'/CA | 0(?) | 140
Steel Assembly | RIGID_FRAME | 161.5 | +7.950 | +8.100 | C8/CA-CB | L0(?) | 70
Steel Assembly | RIGID_FRAME | 57.2 | +8.050 | +8.100 | C8-C8'/CA-CB | S0(?) | 50
Steel Assembly | RIGID_FRAME | 165.7 | +7.950 | +8.100 | C6/CA-CB | L0(?) | 70
Steel Assembly | RIGID_FRAME | 57.2 | +8.050 | +8.100 | C6-C7/CA-CB | S0(?) | 50
Steel Assembly | RIGID_FRAME | 2.2 | +7.858 | +8.058 | C6/CA | 0(?) | 10
Steel Assembly | RIGID_FRAME | 164.7 | +7.950 | +8.100 | C4/CA-CB | L0(?) | 70
Steel Assembly | RIGID_FRAME | 57.2 | +8.050 | +8.100 | C4-C5/CA-CB | S0(?) | 50
Steel Assembly | RIGID_FRAME | 247.3 | +7.940 | +8.240 | C4-C5/CA-CB | L0(?) | 82.5
Steel Assembly | RIGID_FRAME | 19.3 | +6.020 | +8.420 | C7/CA | F0(?) | 130
Steel Assembly | RIGID_FRAME | 24.1 | +3.020 | +6.020 | C7/CA | F0(?) | 130
Steel Assembly | RIGID_FRAME | 24.1 | +0.020 | +3.020 | C7/CA | F0(?) | 130
Steel Assembly | RIGID_FRAME | 19.3 | +6.020 | +8.420 | C4/CA | F0(?) | 130
Steel Assembly | RIGID_FRAME | 24.1 | +3.020 | +6.020 | C4/CA | F0(?) | 130
Steel Assembly | RIGID_FRAME | 24.1 | +0.020 | +3.020 | C4/CA | F0(?) | 130
Steel Assembly | RIGID_FRAME | 21.2 | +7.447 | +7.617 | C3-C4/CA-CB | S0(?) | 50
Steel Assembly | RIGID_FRAME | 21.2 | +7.447 | +7.616 | C3-C4/CA-CB | S0(?) | 50
Steel Assembly | RIGID_FRAME | 21.6 | +7.447 | +7.617 | C2-C3/CA-CB | S0(?) | 50
Steel Assembly | RIGID_FRAME | 21.6 | +7.447 | +7.616 | C2-C3/CA-CB | S0(?) | 50
Steel Assembly | RIGID_FRAME | 20.8 | +7.450 | +7.616 | C1-C2/CA-CB | S0(?) | 50
Steel Assembly | RIGID_FRAME | 20.8 | +7.450 | +7.617 | C1-C2/CA-CB | S0(?) | 50
Steel Assembly | RIGID_FRAME | 21 | +7.566 | +7.736 | C1-C2/CA-CB | S0(?) | 50
Steel Assembly | RIGID_FRAME | 21 | +7.566 | +7.737 | C1-C2/CA-CB | S0(?) | 50
Steel Assembly | RIGID_FRAME | 21 | +7.686 | +7.855 | C1-C2/CA-CB | S0(?) | 50
Steel Assembly | RIGID_FRAME | 21 | +7.686 | +7.856 | C1-C2/CA-CB | S0(?) | 50
Steel Assembly | RIGID_FRAME | 21 | +7.805 | +7.974 | C1-C2/CA-CB | S0(?) | 50
Steel Assembly | RIGID_FRAME | 21 | +7.805 | +7.976 | C1-C2/CA-CB | S0(?) | 50
Steel Assembly | RIGID_FRAME | 19.4 | +8.550 | +10.205 | C8/CA | M0(?) | 100
Steel Assembly | RIGID_FRAME | 19.4 | +8.550 | +10.205 | C8/CB | M0(?) | 100
Steel Assembly | RIGID_FRAME | 28.9 | +8.550 | +11.020 | C6/CA | M0(?) | 100
Steel Assembly | RIGID_FRAME | 28.9 | +8.550 | +11.020 | C6/CB | M0(?) | 100
Steel Assembly | RIGID_FRAME | 38.2 | +8.550 | +11.820 | C4/CA | M0(?) | 100
Steel Assembly | RIGID_FRAME | 38.2 | +8.550 | +11.820 | C4/CB | M0(?) | 100
Steel Assembly | RIGID_FRAME | 179.4 | +10.205 | +10.305 | C8/CA-CB | L0(?) | 100
Steel Assembly | RIGID_FRAME | 179.4 | +11.020 | +11.120 | C6/CA-CB | L0(?) | 100
Steel Assembly | RIGID_FRAME | 179.4 | +11.820 | +11.920 | C4/CA-CB | L0(?) | 100
Steel Assembly | RIGID_FRAME | 23.4 | +2.900 | +4.900 | C8'/CA | M0(?) | 100
Steel Assembly | RIGID_FRAME | 23.4 | +2.900 | +4.900 | C8-C8'/CA | M0(?) | 100
Steel Assembly | RIGID_FRAME | 24.6 | +5.000 | +7.100 | C7-C8/CA | M0(?) | 100
Steel Assembly | RIGID_FRAME | 20 | +1.100 | +2.800 | C8-C8'/CA | M0(?) | 100
Steel Assembly | RIGID_FRAME | 20 | +1.100 | +2.800 | C7-C8/CA | M0(?) | 100
Steel Assembly | RIGID_FRAME | 62.6 | +4.900 | +5.000 | C8-C9/CA | L0(?) | 100
Steel Assembly | RIGID_FRAME | 62.6 | +2.800 | +2.900 | C8-C9/CA | L0(?) | 100
Steel Assembly | RIGID_FRAME | 62.6 | +1.000 | +1.100 | C8-C9/CA | L0(?) | 100
Steel Assembly | RIGID_FRAME | 59.7 | +7.100 | +7.200 | C7-C8/CA | L0(?) | 100
Steel Assembly | RIGID_FRAME | 59.7 | +4.900 | +5.000 | C7-C8/CA | L0(?) | 100
Steel Assembly | RIGID_FRAME | 59.7 | +2.800 | +2.900 | C7-C8/CA | L0(?) | 100
Steel Assembly | RIGID_FRAME | 59.7 | +1.000 | +1.100 | C7-C8/CA | L0(?) | 100
Steel Assembly | RIGID_FRAME | 23.4 | +2.900 | +4.900 | C3-C4/CA | M0(?) | 100
Steel Assembly | RIGID_FRAME | 20 | +1.100 | +2.800 | C1-C2/CA | M0(?) | 100
Steel Assembly | RIGID_FRAME | 24.6 | +5.000 | +7.100 | C2-C3/CA | M0(?) | 100
Steel Assembly | RIGID_FRAME | 24.6 | +5.000 | +7.100 | C1-C2/CA | M0(?) | 100
Steel Assembly | RIGID_FRAME | 50.3 | +7.100 | +7.200 | C2-C3/CA | L0(?) | 100
Steel Assembly | RIGID_FRAME | 50.3 | +4.900 | +5.000 | C2-C3/CA | L0(?) | 100
Steel Assembly | RIGID_FRAME | 45.6 | +4.900 | +5.000 | C3-C4/CA | L0(?) | 100
Steel Assembly | RIGID_FRAME | 45.6 | +2.800 | +2.900 | C3-C4/CA | L0(?) | 100
Steel Assembly | RIGID_FRAME | 50.3 | +2.800 | +2.900 | C2-C3/CA | L0(?) | 100
Steel Assembly | RIGID_FRAME | 50.3 | +1.000 | +1.100 | C2-C3/CA | L0(?) | 100
Steel Assembly | RIGID_FRAME | 48.9 | +7.100 | +7.200 | C1-C2/CA | L0(?) | 100
Steel Assembly | RIGID_FRAME | 48.9 | +4.900 | +5.000 | C1-C2/CA | L0(?) | 100
Steel Assembly | RIGID_FRAME | 48.9 | +2.800 | +2.900 | C1-C2/CA | L0(?) | 100
Steel Assembly | RIGID_FRAME | 48.9 | +1.000 | +1.100 | C1-C2/CA | L0(?) | 100
Steel Assembly | RIGID_FRAME | 0.3 | +6.088 | +6.091 | C1/CB | 0(?) | 3
Steel Assembly | RIGID_FRAME | 0.3 | +3.869 | +3.872 | C1/CB | 0(?) | 3
Steel Assembly | RIGID_FRAME | 0.5 | +1.047 | +1.052 | C1/CB | 0(?) | 5
Steel Assembly | RIGID_FRAME | 0.5 | +1.897 | +1.902 | C1/CB | 0(?) | 5
Steel Assembly | RIGID_FRAME | 0.5 | +0.197 | +0.202 | C1/CB | 0(?) | 5
Steel Assembly | RIGID_FRAME | 13.9 | -0.000 | +2.150 | C1/CB | 0(?) | 80
2 x Steel Assembly | RIGID_FRAME | 44.4 | +7.100 | +7.200 | C1/CA-CB | L0(?) | 100
Steel Assembly | RIGID_FRAME | 41.9 | +7.100 | +7.200 | C1/CA-CB | L0(?) | 100
Steel Assembly | RIGID_FRAME | 41.9 | +2.760 | +2.860 | C1/CA-CB | L0(?) | 100
2 x Steel Assembly | RIGID_FRAME | 44.4 | +2.760 | +2.860 | C1/CA-CB | L0(?) | 100
Steel Assembly | RIGID_FRAME | 9.9 | +7.390 | +8.440 | 1/E | F0(?) | 80
Steel Assembly | RIGID_FRAME | 5.5 | +7.860 | +8.440 | C1/CA | F0(?) | 80
Steel Assembly | RIGID_FRAME | 14.8 | +6.000 | +7.680 | C1/CA | F0(?) | 80
Steel Assembly | RIGID_FRAME | 11.8 | +6.000 | +7.340 | 1/E | F0(?) | 80
Steel Assembly | RIGID_FRAME | 26.4 | +3.000 | +6.000 | C1/CA | F0(?) | 80
Steel Assembly | RIGID_FRAME | 26.4 | +3.000 | +6.000 | 1/E | F0(?) | 80
Steel Assembly | RIGID_FRAME | 0.3 | +6.898 | +6.901 | C1/CB | 0(?) | 3
Steel Assembly | RIGID_FRAME | 0.3 | +5.279 | +5.282 | C1/CB | 0(?) | 3
Steel Assembly | RIGID_FRAME | 0.3 | +4.679 | +4.682 | C1/CB | 0(?) | 3
Steel Assembly | RIGID_FRAME | 0.3 | +3.059 | +3.062 | C1/CB | 0(?) | 3
Steel Assembly | RIGID_FRAME | 14.3 | +4.980 | +7.200 | C1/CB | 0(?) | 80
Steel Assembly | RIGID_FRAME | 14.3 | +2.760 | +4.980 | C1/CB | 0(?) | 80
Steel Assembly | RIGID_FRAME | 49.6 | +2.860 | +7.100 | C1/CA-CB | M0(?) | 100
Steel Assembly | RIGID_FRAME | 40.8 | +7.100 | +7.200 | C1/CA-CB | L0(?) | 100
Steel Assembly | RIGID_FRAME | 40.8 | +2.760 | +2.860 | C1/CA-CB | L0(?) | 100
Steel Assembly | RIGID_FRAME | 26.4 | +0.000 | +3.000 | C1/CA | F0(?) | 80
Steel Assembly | RIGID_FRAME | 26.4 | -0.000 | +3.000 | 1/E | F0(?) | 80
Steel Assembly | RIGID_FRAME | 32 | +2.100 | +2.150 | C1/CA-CB | L0(?) | 50
2 x Steel Assembly | RIGID_FRAME | 33.3 | +8.456 | +10.494 | C8-C8'/CA-CB | S0(?) | 50
2 x Steel Assembly | RIGID_FRAME | 33.3 | +8.456 | +10.511 | C8-C8'/CA-CB | S0(?) | 50
4 x Steel Assembly | RIGID_FRAME | 16 | +9.844 | +9.898 | C6-C7/CA-CB | B0(?) | 40
2 x Steel Assembly | RIGID_FRAME | 36.7 | +8.458 | +11.324 | C6-C7/CA-CB | S0(?) | 50
2 x Steel Assembly | RIGID_FRAME | 36.7 | +8.474 | +11.324 | C6-C7/CA-CB | S0(?) | 50
4 x Steel Assembly | RIGID_FRAME | 16 | +10.247 | +10.301 | C4-C5/CA-CB | B0(?) | 40
2 x Steel Assembly | RIGID_FRAME | 40.9 | +8.447 | +12.101 | C4-C5/CA-CB | S0(?) | 50
2 x Steel Assembly | RIGID_FRAME | 40.9 | +8.462 | +12.101 | C4-C5/CA-CB | S0(?) | 50
Steel Assembly | RIGID_FRAME | 23.2 | +8.023 | +8.197 | C5/CA-CB | L0(?) | 50
Steel Assembly | RIGID_FRAME | 22.3 | +8.147 | +8.316 | C5/CA-CB | L0(?) | 50
Steel Assembly | RIGID_FRAME | 22.3 | +8.266 | +8.436 | C5/CA-CB | L0(?) | 50
Steel Assembly | RIGID_FRAME | 23.2 | +8.023 | +8.197 | C4/CA-CB | L0(?) | 50
Steel Assembly | RIGID_FRAME | 22.3 | +8.147 | +8.316 | C4/CA-CB | L0(?) | 50
Steel Assembly | RIGID_FRAME | 22.3 | +8.266 | +8.436 | C4/CA-CB | L0(?) | 50
Steel Assembly | RIGID_FRAME | 22.3 | +8.028 | +8.197 | C1/CA-CB | L0(?) | 50
Steel Assembly | RIGID_FRAME | 22.3 | +8.147 | +8.316 | C1/CA-CB | L0(?) | 50
Steel Assembly | RIGID_FRAME | 22.3 | +8.266 | +8.436 | C1/CA-CB | L0(?) | 50
Steel Assembly | RIGID_FRAME | 38.5 | +8.275 | +8.545 | C5-C6/CA | 0(?) | 5
Steel Assembly | RIGID_FRAME | 49.3 | +5.000 | +10.340 | C4-C5/CA | M0(?) | 80
Steel Assembly | RIGID_FRAME | 180.5 | +8.450 | +8.550 | C8/CA-CB | L0(?) | 100
Steel Assembly | RIGID_FRAME | 178.4 | +8.450 | +8.550 | C6/CA-CB | L0(?) | 100
Steel Assembly | RIGID_FRAME | 1114.4 | -0.250 | +8.550 | C7/CA | PT0(?) | 334.997
Steel Assembly | RIGID_FRAME | 1114.4 | -0.250 | +8.550 | C4/CA | PT0(?) | 334.997
Steel Assembly | RIGID_FRAME | 36 | +8.470 | +8.550 | C5-C6/CA | L0(?) | 80
Steel Assembly | RIGID_FRAME | 32.7 | +5.000 | +8.550 | C5/CA | M0(?) | 80
Steel Assembly | RIGID_FRAME | 7.6 | +8.440 | +8.450 | C8/CA | 0(?) | 10
Steel Assembly | RIGID_FRAME | 123.3 | +8.450 | +8.550 | C7-C9/CA | L0(?) | 100
Steel Assembly | RIGID_FRAME | 5.1 | +8.030 | +8.055 | C9/CA | 0(?) | 10
Steel Assembly | RIGID_FRAME | 11.6 | +7.451 | +7.573 | 7-8/E | PN0(?) | 64
Steel Assembly | RIGID_FRAME | 11.6 | +7.571 | +7.693 | C8'-C9/CA-CB | PN0(?) | 64
Steel Assembly | RIGID_FRAME | 11.6 | +7.690 | +7.812 | C8'-C9/CA-CB | PN0(?) | 64
Steel Assembly | RIGID_FRAME | 11.6 | +7.810 | +7.932 | C8'-C9/CA-CB | PN0(?) | 64
Steel Assembly | RIGID_FRAME | 190.1 | +7.778 | +8.052 | C8-C9/CA | PN0(?) | 135
4 x Steel Assembly | RIGID_FRAME | 43.4 | +8.450 | +8.550 | C8'/CA-CB | L0(?) | 100
3 x Steel Assembly | RIGID_FRAME | 43.2 | +8.450 | +8.550 | C7/CA-CB | L0(?) | 100
Steel Assembly | RIGID_FRAME | 43.8 | +8.450 | +8.550 | C7/CA-CB | L0(?) | 100
3 x Steel Assembly | RIGID_FRAME | 42.9 | +8.450 | +8.550 | C5/CA-CB | L0(?) | 100
Steel Assembly | RIGID_FRAME | 112.9 | +8.050 | +10.556 | C8-C8'/CA | TS0(?) | 100
Steel Assembly | RIGID_FRAME | 123.6 | +7.572 | +10.556 | 6-8/E | TS0(?) | 100
Steel Assembly | RIGID_FRAME | 120.9 | +7.692 | +10.556 | C8-C8'/CA-CB | TS0(?) | 100
Steel Assembly | RIGID_FRAME | 118.2 | +7.811 | +10.556 | C8-C8'/CA-CB | TS0(?) | 100
Steel Assembly | RIGID_FRAME | 115.6 | +7.931 | +10.556 | C8-C8'/CA-CB | TS0(?) | 100
Steel Assembly | RIGID_FRAME | 137.1 | +8.550 | +11.369 | C6-C7/CA | TS0(?) | 100
Steel Assembly | RIGID_FRAME | 158.9 | +7.572 | +11.369 | 4-6/E | TS0(?) | 100
Steel Assembly | RIGID_FRAME | 156.3 | +7.692 | +11.369 | C6-C7/CA-CB | TS0(?) | 100
Steel Assembly | RIGID_FRAME | 153.6 | +7.811 | +11.369 | C6-C7/CA-CB | TS0(?) | 100
Steel Assembly | RIGID_FRAME | 42.5 | +8.450 | +8.550 | C5/CA-CB | L0(?) | 100
Steel Assembly | RIGID_FRAME | 150.9 | +7.931 | +11.369 | C6-C7/CA-CB | TS0(?) | 100
Steel Assembly | RIGID_FRAME | 239.6 | +8.550 | +12.170 | C4-C5/CA | TS0(?) | 120
Steel Assembly | RIGID_FRAME | 258.7 | +7.931 | +12.170 | C4-C5/CA-CB | TS0(?) | 120
Steel Assembly | RIGID_FRAME | 269.6 | +7.572 | +12.170 | 2-4/E | TS0(?) | 120
Steel Assembly | RIGID_FRAME | 266 | +7.692 | +12.170 | C4-C5/CA-CB | TS0(?) | 120
Steel Assembly | RIGID_FRAME | 262.3 | +7.811 | +12.170 | C4-C5/CA-CB | TS0(?) | 120
Steel Assembly | RIGID_FRAME | 116.6 | +7.371 | +7.574 | 6-7/E | PN0(?) | 100
Steel Assembly | RIGID_FRAME | 116.6 | +7.490 | +7.693 | C7-C8/CA-CB | PN0(?) | 100
Steel Assembly | RIGID_FRAME | 116.6 | +7.610 | +7.813 | C7-C8/CA-CB | PN0(?) | 100
Steel Assembly | RIGID_FRAME | 116.6 | +7.729 | +7.932 | C7-C8/CA-CB | PN0(?) | 100
Steel Assembly | RIGID_FRAME | 114 | +7.848 | +8.051 | C7-C8/CA | PN0(?) | 100
Steel Assembly | RIGID_FRAME | 70 | +7.391 | +7.574 | 4-5/E | PN0(?) | 91
Steel Assembly | RIGID_FRAME | 70 | +7.510 | +7.693 | C5-C6/CA-CB | PN0(?) | 91
Steel Assembly | RIGID_FRAME | 70 | +7.630 | +7.813 | C5-C6/CA-CB | PN0(?) | 91
Steel Assembly | RIGID_FRAME | 70 | +7.749 | +7.932 | C5-C6/CA-CB | PN0(?) | 91
Steel Assembly | RIGID_FRAME | 70 | +7.862 | +8.045 | C5-C6/CA | PN0(?) | 91
Steel Assembly | RIGID_FRAME | 178.4 | +8.450 | +8.550 | C4/CA-CB | L0(?) | 100
Steel Assembly | RIGID_FRAME | 145.7 | +8.450 | +8.550 | C1-C4/CA | L0(?) | 100
Steel Assembly | RIGID_FRAME | 785.7 | -0.250 | +8.445 | C2/CA | PT0(?) | 310
Steel Assembly | RIGID_FRAME | 89.9 | +7.371 | +7.574 | 2-3/E | PN0(?) | 100
Steel Assembly | RIGID_FRAME | 91.5 | +7.371 | +7.574 | 1-3/E | PN0(?) | 100
Steel Assembly | RIGID_FRAME | 89.9 | +7.490 | +7.693 | C3-C4/CA-CB | PN0(?) | 100
Steel Assembly | RIGID_FRAME | 91.5 | +7.490 | +7.693 | C2-C3/CA-CB | PN0(?) | 100
Steel Assembly | RIGID_FRAME | 89.9 | +7.610 | +7.813 | C3-C4/CA-CB | PN0(?) | 100
Steel Assembly | RIGID_FRAME | 91.5 | +7.610 | +7.813 | C2-C3/CA-CB | PN0(?) | 100
Steel Assembly | RIGID_FRAME | 89.9 | +7.729 | +7.932 | C3-C4/CA-CB | PN0(?) | 100
Steel Assembly | RIGID_FRAME | 91.5 | +7.729 | +7.932 | C2-C3/CA-CB | PN0(?) | 100
Steel Assembly | RIGID_FRAME | 84.7 | +7.848 | +8.051 | C3-C4/CA | PN0(?) | 100
Steel Assembly | RIGID_FRAME | 91.5 | +7.848 | +8.051 | C2-C3/CA | PN0(?) | 100
4 x Steel Assembly | RIGID_FRAME | 45.7 | +7.219 | +10.454 | C8/CA-CB | D0(?) | 80
3 x Steel Assembly | RIGID_FRAME | 78.3 | +7.250 | +10.423 | C8/CA-CB | M0(?) | 140
Steel Assembly | RIGID_FRAME | 78.3 | +7.250 | +10.423 | C8/CB | M0(?) | 140
Steel Assembly | RIGID_FRAME | 48.7 | +8.450 | +10.423 | C8/CA | M0(?) | 140
Steel Assembly | RIGID_FRAME | 382.8 | +10.423 | +10.556 | C8/CA-CB | L0(?) | 140
4 x Steel Assembly | RIGID_FRAME | 50.8 | +7.222 | +11.264 | C6/CA-CB | D0(?) | 80
3 x Steel Assembly | RIGID_FRAME | 98.3 | +7.250 | +11.236 | C6/CA-CB | M0(?) | 140
Steel Assembly | RIGID_FRAME | 98.3 | +7.250 | +11.236 | C6/CB | M0(?) | 140
Steel Assembly | RIGID_FRAME | 66.2 | +8.550 | +11.236 | C6/CA | M0(?) | 140
Steel Assembly | RIGID_FRAME | 382.8 | +11.236 | +11.369 | C6/CA-CB | L0(?) | 140
4 x Steel Assembly | RIGID_FRAME | 56.4 | +7.225 | +12.062 | C4/CA-CB | D0(?) | 80
3 x Steel Assembly | RIGID_FRAME | 118.2 | +7.250 | +12.037 | C4/CA-CB | M0(?) | 140
Steel Assembly | RIGID_FRAME | 118.2 | +7.250 | +12.037 | C4/CB | M0(?) | 140
Steel Assembly | RIGID_FRAME | 86 | +8.550 | +12.037 | C4/CA | M0(?) | 140
Steel Assembly | RIGID_FRAME | 382.8 | +12.037 | +12.170 | C4/CA-CB | L0(?) | 140
Steel Assembly | RIGID_FRAME | 9.6 | +8.051 | +8.445 | C9/CA | 0(?) | 140
Steel Assembly | RIGID_FRAME | 4.9 | +7.861 | +8.048 | C6/CA | 0(?) | 70
Steel Assembly | RIGID_FRAME | 1608.9 | +7.017 | +8.047 | C5/CA-CB | T0(?) | 210
Steel Assembly | RIGID_FRAME | 1617.3 | +7.017 | +8.050 | C7/CA-CB | T0(?) | 210
Steel Assembly | RIGID_FRAME | 542.6 | +7.297 | +8.040 | C9/CA-CB | T0(?) | 135
Steel Assembly | RIGID_FRAME | 1192.2 | +7.117 | +8.050 | C8'/CA-CB | T0(?) | 190
Steel Assembly | RIGID_FRAME | 13.3 | -0.650 | -0.150 | C9/CA | PS3 | 500
Steel Assembly | RIGID_FRAME | 13.3 | -0.650 | -0.150 | C8/CA | PS3 | 500
Steel Assembly | RIGID_FRAME | 13.3 | -0.650 | -0.150 | C4/CA | PS3 | 500
Steel Assembly | RIGID_FRAME | 13.3 | -0.650 | -0.150 | C7/CA | PS3 | 500
Steel Assembly | RIGID_FRAME | 11 | -0.650 | -0.150 | C3/CA | PS2 | 500
Steel Assembly | RIGID_FRAME | 11 | -0.650 | -0.150 | C2/CA | PS2 | 500
Steel Assembly | RIGID_FRAME | 11 | -0.650 | -0.150 | C1/CA | PS2 | 500
2 x Steel Assembly | RIGID_FRAME | 6.8 | -0.250 | -0.100 | C1/CA | A0(?) | 150
2 x Steel Assembly | RIGID_FRAME | 6.8 | -0.250 | -0.100 | 1/E | A0(?) | 150
6 x Steel Assembly | RIGID_FRAME | 6.8 | -0.250 | -0.100 | C1/CA-CB | A0(?) | 150
Steel Assembly | RIGID_FRAME | 67.2 | +7.302 | +7.611 | C1/CA-CB | RP0(?) | 80
Steel Assembly | RIGID_FRAME | 293.8 | -0.230 | +7.925 | C1/CA-CB | PT0(?) | 135
Steel Assembly | RIGID_FRAME | 289.5 | -0.230 | +7.805 | C1/CA-CB | PT0(?) | 135
Steel Assembly | RIGID_FRAME | 285.2 | -0.230 | +7.685 | C1/CA-CB | PT0(?) | 135
Steel Assembly | RIGID_FRAME | 88.9 | +7.729 | +7.932 | C1-C2/CA-CB | PN0(?) | 100
Steel Assembly | RIGID_FRAME | 88.9 | +7.610 | +7.813 | C1-C2/CA-CB | PN0(?) | 100
Steel Assembly | RIGID_FRAME | 88.9 | +7.490 | +7.693 | C1-C2/CA-CB | PN0(?) | 100
Steel Assembly | RIGID_FRAME | 92.3 | +7.374 | +7.577 | 1-2/E | PN0(?) | 100
Steel Assembly | RIGID_FRAME | 92.3 | +7.848 | +8.051 | C1-C2/CA | PN0(?) | 100
Steel Assembly | RIGID_FRAME | 68 | +7.531 | +7.843 | C1/CA-CB | RP0(?) | 80
Steel Assembly | RIGID_FRAME | 1168.1 | +7.117 | +8.040 | C2/CA-CB | T0(?) | 190
POUTRE | REINFORCEMENT_UNIT | 20484.3 | +0.000 | +4.550 | 1-2/E-A | Po0(?) | 200 | Tekla Assemblages - Poids ferraillage Elément béton: 0 kg
POUTRE | REINFORCEMENT_UNIT | 141998 | +0.000 | +8.550 | 3-9/A | Po0(?) | 200 | Tekla Assemblages - Poids ferraillage Elément béton: 0 kg
POUTRE | REINFORCEMENT_UNIT | 38782.8 | +0.000 | +8.550 | 9/E-A | Po0(?) | 200 | Tekla Assemblages - Poids ferraillage Elément béton: 0 kg
POUTRE | REINFORCEMENT_UNIT | 201869 | +0.000 | +8.550 | 1-9/E | Po0(?) | 200 | Tekla Assemblages - Poids ferraillage Elément béton: 0 kg
Steel Assembly | RIGID_FRAME | 504.1 | -0.230 | +7.370 | C1/CB | PT0(?) | 180
Steel Assembly | RIGID_FRAME | 535.3 | -0.230 | +7.840 | C1/CA | PT0(?) | 180

# IfcMechanicalFastener: Bolt assembly (162)
In: Undefined
Tekla Boulons - Trou oblong Y: 0 mm; Lieu Boulonnage: Montage
Name | NominalDiameter (mm) = Diamètre rondelle (mm) | NominalLength (mm) = Longueur (mm) | Material | Quantité de rondelle | Type rondelle | Nom rondelle | Quantité d'écrou | Type écrou | Nom écrou | Trou oblong X (mm) | Diamètre du trou (mm) | Quantité | Diamètre (mm) | Standard | Nom
5 x Bolt assembly | 12 | 30 | 8.8-SB-Z | 0 | PLA-8.8 | RONDELLE-M12-PLA-8.8 | 4 | E-8.8 | ECROU-M12-E-8.8 | 0 | 14 | 4 | 12 | 8.8-SB-Z | M12*30
3 x Bolt assembly | 20 | 60 | HR10.9 | 4 | PLA-HR10.9 | RONDELLE-M20-PLA-HR10.9 | 2 | E-HR10.9 | ECROU-M20-E-HR10.9 | 22 | 22 | 2 | 20 | HR10.9 | M20*60
13 x Bolt assembly | 20 | 5.5 | 6.8 | 0 | PLA-6.8 | RONDELLE-M20-PLA-6.8 | 0 | E-6.8 | ECROU-M20-E-6.8 | 0 | 22 | 1 | 22 | 6.8 | M20*40
14 x Bolt assembly | 30 | 15 | 6.8 | 0 | PLA-6.8 | RONDELLE-M30-PLA-6.8 | 0 | E-6.8 | ECROU-M30-E-6.8 | 0 | 80 | 1 | 80 | 6.8 | M30*90
15 x Bolt assembly | 16 | 146.2 | INOX_A4 | 0 | PLA-INOXA4 | RONDELLE16-PLA-INOX A4 | 2 | INOX A4 | ECROU16-INOX A4 | 0 | 18 | 2 | 16 | HST-R | HILTI_HST_M16_140/25
3 x Bolt assembly | 16 | 60 | HR10.9 | 4 | PLA-HR10.9 | RONDELLE-M16-PLA-HR10.9 | 2 | E-HR10.9 | ECROU-M16-E-HR10.9 | 18 | 18 | 2 | 16 | HR10.9 | M16*60
5 x Bolt assembly | 16 | 60 | HR10.9 | 6 | PLA-HR10.9 | RONDELLE-M16-PLA-HR10.9 | 3 | E-HR10.9 | ECROU-M16-E-HR10.9 | 18 | 18 | 3 | 16 | HR10.9 | M16*60
2 x Bolt assembly | 12 | 112.2 | INOX_A4 | 0 | PLA-INOXA4 | RONDELLE12-PLA-INOX A4 | 2 | INOX A4 | ECROU12-INOX A4 | 0 | 14 | 2 | 12 | HST-R | HILTI_HST_M12_115/20
2 x Bolt assembly | 12 | 40 | 8.8-SB-Z | 2 | PLA-8.8 | RONDELLE-M12-PLA-8.8 | 2 | E-8.8 | ECROU-M12-E-8.8 | 14 | 14 | 2 | 12 | 8.8-SB-Z | M12*40
2 x Bolt assembly | 30 | 4 | 6.8 | 0 | PLA-6.8 | RONDELLE-M30-PLA-6.8 | 0 | E-6.8 | ECROU-M30-E-6.8 | 0 | 30 | 2 | 30 | 6.8 | M30*90
3 x Bolt assembly | 16 | 50 | HR10.9 | 8 | PLA-HR10.9 | RONDELLE-M16-PLA-HR10.9 | 4 | E-HR10.9 | ECROU-M16-E-HR10.9 | 18 | 18 | 4 | 16 | HR10.9 | M16*50
Bolt assembly | 16 | 50 | HR10.9 | 4 | PLA-HR10.9 | RONDELLE-M16-PLA-HR10.9 | 2 | E-HR10.9 | ECROU-M16-E-HR10.9 | 18 | 18 | 2 | 16 | HR10.9 | M16*50
Bolt assembly | 16 | 60 | HR10.9 | 4 | PLA-HR10.9 | RONDELLE-M16-PLA-HR10.9 | 2 | E-HR10.9 | ECROU-M16-E-HR10.9 | 0 | 18 | 2 | 16 | HR10.9 | M16*60
Bolt assembly | 16 | 50 | HR10.9 | 4 | PLA-HR10.9 | RONDELLE-M16-PLA-HR10.9 | 2 | E-HR10.9 | ECROU-M16-E-HR10.9 | 0 | 18 | 2 | 16 | HR10.9 | M16*50
Bolt assembly | 16 | 70 | HR10.9 | 4 | PLA-HR10.9 | RONDELLE-M16-PLA-HR10.9 | 2 | E-HR10.9 | ECROU-M16-E-HR10.9 | 18 | 18 | 2 | 16 | HR10.9 | M16*70
Bolt assembly | 20 | 5 | 6.8 | 0 | PLA-6.8 | RONDELLE-M20-PLA-6.8 | 0 | E-6.8 | ECROU-M20-E-6.8 | 0 | 22 | 1 | 22 | 6.8 | M20*40
22 x Bolt assembly | 24 | 15 | 6.8 | 0 | PLA-6.8 | RONDELLE-M24-PLA-6.8 | 0 | E-6.8 | ECROU-M24-E-6.8 | 0 | 26 | 1 | 26 | 6.8 | M24*50
22 x Bolt assembly | 22 | 15 | 6.8 | 0 | PLA-6.8 | RONDELLE-M22-PLA-6.8 | 0 | E-6.8 | ECROU-M22-E-6.8 | 0 | 24 | 1 | 24 | 6.8 | M22*40
11 x Bolt assembly | 8 | 10 | 6.8 | 0 | PLA-6.8 | RONDELLE-M8-PLA-6.8 | 0 | E-6.8 | ECROU-M8-E-6.8 | 0 | 10 | 1 | 10 | 6.8 | M8*12
11 x Bolt assembly | 24 | 10 | 6.8 | 0 | PLA-6.8 | RONDELLE-M24-PLA-6.8 | 0 | E-6.8 | ECROU-M24-E-6.8 | 0 | 26 | 2 | 26 | 6.8 | M24*50
5 x Bolt assembly | 12 | 89.2 | INOX_A4 | 0 | PLA-INOXA4 | RONDELLE12-PLA-INOX A4 | 2 | INOX A4 | ECROU12-INOX A4 | 0 | 14 | 2 | 12 | HSA-R | HILTI_HSA_M12X100
4 x Bolt assembly | 16 | 146.2 | INOX_A4 | 0 | PLA-INOXA4 | RONDELLE16-PLA-INOX A4 | 1 | INOX A4 | ECROU16-INOX A4 | 0 | 18 | 1 | 16 | HST-R | HILTI_HST_M16_140/25
2 x Bolt assembly | 16 | 60 | 8.8-G | 0 | PLA-8.8 | RONDELLE-M16-PLA-8.8 | 2 | E-8.8 | ECROU-M16-E-8.8 | 0 | 18 | 2 | 16 | 8.8-G | M16*60
5 x Bolt assembly | 16 | 60 | 8.8-SB-Z | 0 | PLA-8.8 | RONDELLE-M16-PLA-8.8 | 2 | E-8.8 | ECROU-M16-E-8.8 | 0 | 18 | 2 | 16 | 8.8-SB-Z | M16*60
8 x Bolt assembly | 30 | 15 | 6.8 | 0 | PLA-6.8 | RONDELLE-M30-PLA-6.8 | 0 | E-6.8 | ECROU-M30-E-6.8 | 0 | 50 | 1 | 50 | 6.8 | M30*90

# IfcMember: IPE200 (10)
In: Undefined
Description: IPE200; Material: STEEL/S275-E28
Tekla Commun - Repère d'assemblage: TS0(?); Phase: 1; Classe: 2; Matériau: S275-E28; Profil: IPE200; Nom: TRAVERSE SHED
Tekla Quantités - Volume: 0 m3; Surface supérieure totale: 0 m2; Surface par tonne: 34.3 m2; Hauteur: 200 mm; Largeur: 100 mm
Pset_MemberCommon - LoadBearing: yes
BaseQuantities - CrossSectionArea: 0.00285 m2
Name | Niveau bas | Niveau haut | Repère de pièce = Reference | Poids (kg) | Surface nette (m2) | Longueur (mm) | Length (mm) | OuterSurfaceArea (m2) = GrossSurfaceArea (m2) | NetVolume (m3) | GrossVolume (m3) | NetWeight (kg) | GrossWeight (kg)
5 x TRAVERSE SHED | +8.425 | +10.556 | TS0(?) | 101.7 | 3.5 | 4546.5 | 4546.48 | 3.49169 | 0.0120846 | 0.0129575 | 94.8641 | 101.716
TRAVERSE SHED | +8.550 | +11.369 | TS0 | 137.1 | 4.6 | 6127 | 6127.02 | 4.70555 | 0.0160279 | 0.017462 | 125.819 | 137.077
4 x TRAVERSE SHED | +8.428 | +11.369 | TS0(?) | 137.1 | 4.8 | 6127 | 6127.02 | 4.70555 | 0.016388 | 0.017462 | 128.646 | 137.077

# IfcMember: IPE240 (5)
In: Undefined
Description: IPE240; Material: STEEL/S275-E28
Pset_MemberCommon - LoadBearing: yes
Tekla Commun - Niveau haut: +12.170; Repère d'assemblage: TS0(?); Phase: 1; Classe: 2; Matériau: S275-E28; Profil: IPE240; Nom: TRAVERSE SHED
Tekla Quantités - Poids: 239.6 kg; Volume: 0 m3; Surface supérieure totale: 0 m2; Surface par tonne: 29.9 m2; Hauteur: 240 mm; Largeur: 120 mm; Longueur: 7809.7 mm
BaseQuantities - Length: 7809.66 mm; OuterSurfaceArea: 7.20051 m2; GrossSurfaceArea: 7.20051 m2; CrossSectionArea: 0.003909 m2; GrossVolume: 0.030528 m3; GrossWeight: 239.645 kg
Name | Reference = Repère de pièce | Niveau bas | Surface nette (m2) | NetVolume (m3) | NetWeight (kg)
TRAVERSE SHED | TS0 | +8.550 | 7.1 | 0.0279537 | 219.436
4 x TRAVERSE SHED | TS0(?) | +8.405 | 7.3 | 0.0285365 | 224.011

# IfcMember: L40*4 (2)
In: Undefined
Description: L40*4; Material: STEEL/S235-E24
Tekla Commun - Niveau bas: -0.244; Niveau haut: +2.814; Repère de pièce: S0; Repère d'assemblage: S0(?); Finition: GALVA; Phase: 1; Classe: 2; Matériau: S235-E24; Profil: L40*4; Nom: STABILTE
Tekla Quantités - Poids: 10.5 kg; Volume: 0 m3; Surface supérieure totale: 0 m2; Surface par tonne: 64.1 m2; Surface nette: 0.6 m2; Hauteur: 40 mm; Largeur: 40 mm; Longueur: 4334.8 mm
Pset_MemberCommon - LoadBearing: yes; Reference: S0
BaseQuantities - Length: 4334.85 mm; OuterSurfaceArea: 0.671901 m2; GrossSurfaceArea: 0.671901 m2; CrossSectionArea: 0.000308 m2; NetVolume: 0.00131779 m3; GrossVolume: 0.00133513 m3; NetWeight: 10.3447 kg; GrossWeight: 10.4808 kg

# IfcMember: L70*7 (12)
In: Undefined
Description: L70*7; Material: STEEL/S235-E24
Tekla Commun - Repère d'assemblage: D0(?); Phase: 1; Classe: 2; Matériau: S235-E24; Profil: L70*7; Nom: DIAGONALE
Tekla Quantités - Volume: 0 m3; Surface supérieure totale: 0 m2; Surface par tonne: 36.9 m2; Hauteur: 70 mm; Largeur: 70 mm
Pset_MemberCommon - LoadBearing: yes
BaseQuantities - CrossSectionArea: 0.00094 m2
Name | Niveau bas | Niveau haut | Repère de pièce = Reference | Poids (kg) | Surface nette (m2) | Longueur (mm) | Length (mm) | OuterSurfaceArea (m2) = GrossSurfaceArea (m2) | NetVolume (m3) | GrossVolume (m3) | NetWeight (kg) | GrossWeight (kg)
2 x DIAGONALE | +5.104 | +8.435 | D0(?) | 35 | 1.3 | 4749.5 | 4749.48 | 1.29186 | 0.00442177 | 0.00446451 | 34.7109 | 35.0464
2 x DIAGONALE | +5.105 | +8.435 | D0 | 35 | 1.3 | 4749.5 | 4749.48 | 1.29186 | 0.00442177 | 0.00446451 | 34.7109 | 35.0464
4 x DIAGONALE | +5.112 | +8.428 | D0 | 28.3 | 1.1 | 3821 | 3820.99 | 1.03931 | 0.00355734 | 0.00359173 | 27.9251 | 28.1951
2 x DIAGONALE | +5.108 | +8.432 | D0 | 31.4 | 1.3 | 4251.5 | 4251.52 | 1.15641 | 0.00395816 | 0.00399643 | 31.0716 | 31.3719
2 x DIAGONALE | +5.108 | +8.432 | D0(?) | 31.4 | 1.3 | 4251.5 | 4251.52 | 1.15641 | 0.00395816 | 0.00399643 | 31.0716 | 31.3719

# IfcMember: TUBE-60.3*3.2 (2)
In: Undefined
Description: TUBE-60.3*3.2; Material: STEEL/S235-E24
Pset_MemberCommon - LoadBearing: yes; Reference: B0
Tekla Commun - Niveau bas: +3.034; Niveau haut: +4.925; Repère de pièce: B0; Repère d'assemblage: B0(?); Finition: GALVA; Phase: 1; Classe: 2; Matériau: S235-E24; Profil: TUBE-60.3*3.2; Nom: BUTON
Tekla Quantités - Poids: 14.3 kg; Volume: 0 m3; Surface supérieure totale: 0 m2; Surface par tonne: 42.9 m2; Surface nette: 0.6 m2; Hauteur: 60.3 mm; Largeur: 60.3 mm; Longueur: 3268.2 mm
BaseQuantities - Length: 3268.16 mm; OuterSurfaceArea: 0.615734 m2; GrossSurfaceArea: 0.615734 m2; CrossSectionArea: 0.000559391 m2; NetVolume: 0.00182818 m3; GrossVolume: 0.00182818 m3; NetWeight: 14.3512 kg; GrossWeight: 14.3512 kg

# IfcMember: TUBE-C-80*80*4 (16)
In: Undefined
Description: TUBE-C-80*80*4; Material: STEEL/S235-E24
Tekla Commun - Phase: 1; Classe: 2; Matériau: S235-E24; Profil: TUBE-C-80*80*4
Tekla Quantités - Volume: 0 m3; Surface supérieure totale: 0 m2; Surface par tonne: 33.2 m2; Hauteur: 80 mm; Largeur: 80 mm
Pset_MemberCommon - LoadBearing: yes
BaseQuantities - CrossSectionArea: 0.001175 m2
Name | Niveau bas | Niveau haut | Repère de pièce = Reference | Repère d'assemblage | Nom | Poids (kg) | Surface nette (m2) | Longueur (mm) | Length (mm) | OuterSurfaceArea (m2) = GrossSurfaceArea (m2) | NetVolume (m3) | GrossVolume (m3) | NetWeight (kg) | GrossWeight (kg)
BUTON | +5.103 | +7.192 | B0 | B0(?) | BUTON | 25.7 | 0.9 | 2783.7 | 2783.74 | 0.851823 | 0.00338502 | 0.00327089 | 26.5724 | 25.6765
BUTON | +5.106 | +7.683 | B0 | B0(?) | BUTON | 29.2 | 0.9 | 3162.8 | 3162.79 | 0.967813 | 0.00384595 | 0.00371628 | 30.1907 | 29.1728
BUTON | +5.106 | +7.739 | B0(?) | B0(?) | BUTON | 29.6 | 0.9 | 3208.3 | 3208.27 | 0.981732 | 0.00390126 | 0.00376972 | 30.6249 | 29.5923
BUTON | +5.103 | +7.182 | B0 | B0(?) | BUTON | 25.6 | 0.9 | 2776.8 | 2776.8 | 0.849701 | 0.00337659 | 0.00326274 | 26.5062 | 25.6125
4 x DIAGONALE | +7.219 | +10.454 | D0 | D0(?) | DIAGONALE | 45.7 | 1.6 | 4950.5 | 4950.55 | 1.51487 | 0.00601987 | 0.00581689 | 47.256 | 45.6626
4 x DIAGONALE | +7.222 | +11.264 | D0 | D0(?) | DIAGONALE | 50.8 | 1.7 | 5507.1 | 5507.1 | 1.68517 | 0.00669664 | 0.00647085 | 52.5686 | 50.7962
4 x DIAGONALE | +7.225 | +12.062 | D0 | D0(?) | DIAGONALE | 56.4 | 1.9 | 6111.9 | 6111.9 | 1.87024 | 0.00743208 | 0.00718149 | 58.3418 | 56.3747

# IfcSlab: 200*2637, DALLE
In: Undefined
Description: 200*2637; PredefinedType: FLOOR; Material: CONCRETE/C25/30
Tekla Commun - Niveau bas: +8.550; Niveau haut: +11.187; Repère de pièce: Da0(?); Repère d'assemblage: Da0(?); Phase: 1; Classe: 1; Matériau: C25/30; Profil: 200*2637; Nom: DALLE
Tekla Quantités - Poids: 3377.1 kg; Volume: 1.4 m3; Surface supérieure totale: 0 m2; Surface par tonne: 5 m2; Surface nette: 16.9 m2; Hauteur: 2636.8 mm; Largeur: 200 mm; Longueur: 5336.6 mm
Pset_SlabCommon - LoadBearing: yes; Reference: Da0(?)
BaseQuantities - Width: 200 mm; NetVolume: 1.40714 m3; NetArea: 0 m2; NetWeight: 3377.14 kg

# IfcSlab: 200*3465, DALLE
In: Undefined
Description: 200*3465; PredefinedType: FLOOR; Material: CONCRETE/C25/30
Pset_SlabCommon - LoadBearing: yes; Reference: Da0(?)
Tekla Commun - Niveau bas: +8.550; Niveau haut: +12.015; Repère de pièce: Da0(?); Repère d'assemblage: Da0(?); Phase: 1; Classe: 1; Matériau: C25/30; Profil: 200*3465; Nom: DALLE
Tekla Quantités - Poids: 5561.6 kg; Volume: 2.3 m3; Surface supérieure totale: 0 m2; Surface par tonne: 4.8 m2; Surface nette: 26.7 m2; Hauteur: 3465.3 mm; Largeur: 200 mm; Longueur: 6687.2 mm
BaseQuantities - Width: 200 mm; NetVolume: 2.31732 m3; NetArea: 0 m2; NetWeight: 5561.58 kg

# IfcSlab: 200*4269, DALLE
In: Undefined
Description: 200*4269; PredefinedType: FLOOR; Material: CONCRETE/C25/30
Pset_SlabCommon - LoadBearing: yes; Reference: Da0(?)
Tekla Commun - Niveau bas: +8.550; Niveau haut: +12.819; Repère de pièce: Da0(?); Repère d'assemblage: Da0(?); Phase: 1; Classe: 1; Matériau: C25/30; Profil: 200*4269; Nom: DALLE
Tekla Quantités - Poids: 8363 kg; Volume: 3.5 m3; Surface supérieure totale: 0 m2; Surface par tonne: 4.7 m2; Surface nette: 39.2 m2; Hauteur: 4269.5 mm; Largeur: 200 mm; Longueur: 8161.6 mm
BaseQuantities - Width: 200 mm; NetVolume: 3.48458 m3; NetArea: 0 m2; NetWeight: 8363 kg

# IfcSlab: 230*9250 (3)
In: Undefined
Description: 230*9250; PredefinedType: FLOOR; Material: CONCRETE/C25/30
Pset_SlabCommon - LoadBearing: yes; Reference: Da0(?)
Tekla Commun - Repère de pièce: Da0(?); Repère d'assemblage: Da0(?); Phase: 1; Classe: 1; Matériau: C25/30; Profil: 230*9250; Nom: DALLE
Tekla Quantités - Hauteur: 9250 mm; Largeur: 230 mm
BaseQuantities - Width: 230 mm
Name | Niveau bas | Niveau haut | Poids (kg) = NetWeight (kg) | Volume (m3) | Surface supérieure totale (m2) | Surface par tonne (m2) | Surface nette (m2) | Longueur (mm) | NetVolume (m3) | NetArea (m2)
DALLE | +3.200 | +3.430 | 149095 | 62.1 | 270.1 | 3.7 | 557.9 | 29200 | 62.123 | 270.1
DALLE | +7.830 | +8.060 | 149095 | 62.1 | 270.1 | 3.7 | 557.9 | 29200 | 62.123 | 270.1
DALLE | +3.200 | +3.430 | 71043.3 | 29.6 | 128.7 | 3.8 | 268.1 | 14279.8 | 29.6014 | 128.702

# IfcSlab: 250*9650, DALLE
In: Undefined
Description: 250*9650; PredefinedType: FLOOR; Material: CONCRETE/C25/30
Pset_SlabCommon - LoadBearing: yes; Reference: Da0(?)
Tekla Commun - Niveau bas: -0.250; Niveau haut: +0.000; Repère de pièce: Da0(?); Repère d'assemblage: Da0(?); Phase: 1; Classe: 1; Matériau: C25/30; Profil: 250*9650; Nom: DALLE
Tekla Quantités - Poids: 283214 kg; Volume: 118 m3; Surface supérieure totale: 472 m2; Surface par tonne: 3.4 m2; Surface nette: 973.3 m2; Hauteur: 9650 mm; Largeur: 250 mm; Longueur: 49296.2 mm
BaseQuantities - Width: 250 mm; NetVolume: 118.006 m3; NetArea: 472.023 m2; NetWeight: 283214 kg
